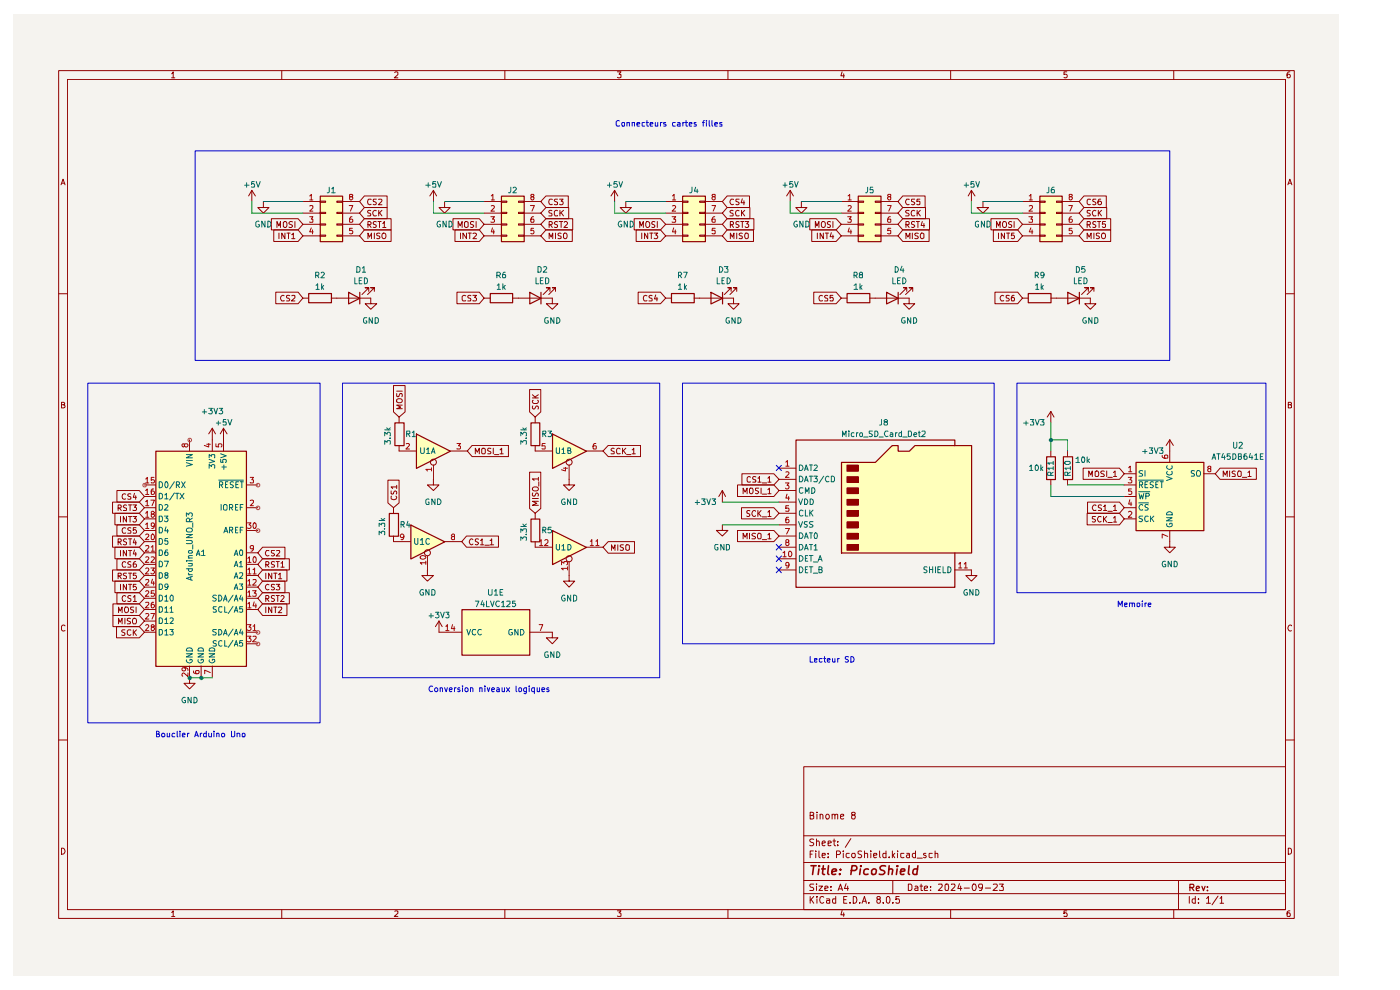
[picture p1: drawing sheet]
<svg xmlns="http://www.w3.org/2000/svg" width="297mm" height="210mm" viewBox="0 0 297 210" stroke-linecap="round" stroke-linejoin="round" font-family="sans-serif">
<path d="M2.9 3h281.2v203.8h-281.2z" fill="#f5f3ef"/>
<g fill="none" stroke="#910000" stroke-width=".21">
<path d="M12.4 15h262.2v179.8h-262.2zM14.3 16.8h258.4v176.2h-258.4zM36.4 15.7l.3-.5v1.3M36.4 16.5h.7M59.8 15v1.8M83.7 15.4l.2-.2h.3l.2 .2v.4l-.8 .7h.8M107.1 15v1.8M131 15.2h.7l-.4 .5 .4 .1v.6h-.7M154.4 15v1.8M178.6 15.2l-.2 .9h.8M179 15.7v.8M201.7 15v1.8"/>
<path d="M226.3 15.2h-.6v.6l.4-.1 .3 .3-.1 .4h-.6M249 15v1.8M273.6 15.2l-.4 .1-.2 .3v.8h.6v-.6l-.4-.1-.2 .3M13 39.2l.4-1.2 .4 1.2M13.1 38.9h.6M273.2 39.2l.4-1.2 .5 1.2M273.3 38.9h.6M12.4 62.3h1.9M272.7 62.3h1.9M13 85.8h.5l.2-.3-.2-.2h-.5v1.2h.5l.3-.4-.3-.3M273.3 85.8h.5l.2-.3-.2-.2h-.5v1.2h.5l.2-.1v-.4l-.3-.2M12.4 109.6h1.9"/>
<path d="M272.7 109.6h1.9M13.8 132.8l-.4-.2-.4 .3 .1 .8 .3 .2 .4-.1M274 132.8l-.2-.2a.6 .6 0 0 0-.6 .7 .6 .6 0 0 0 .8 .5M12.4 157h1.9M272.7 157h1.9M13 179.9a.65 .65 0 0 1 .8 .6 .65 .65 0 0 1-.8 .7zM170.5 162.6h102.2v30.4h-102.2zM170.5 177.3h102.2M171.9 173l.6-.1 .1-.2-.1-.3-.6-.1v1.4h.5l.2-.1v-.5l-.3-.1M172.6 178.1h-.7l-.1 .3 .2 .2 .5 .1 .1 .4-.3 .3-.5-.1M173.2 178.6l.2-.2 .3 .1 .1 .9M173.2 178v1.4"/>
<path d="M173.3 172.3v.1M173.3 172.7v1M174 172.9v-.1a.36 .36 0 0 1 .6 .2v.7M174 172.7v1M174.4 178.9l.7-.2-.2-.3-.4 .1-.1 .7 .3 .2 .3-.1M175.3 172.9l.4-.2a.6 .6 0 0 1 0 1h-.3a.6 .6 0 0 1-.1-.8zM175.7 178.9l.7-.2-.1-.2h-.6v.8h.6M176.5 172.9l.2-.2 .3 .1 .1 .9M176.5 172.7v1M176.7 178.4h.6M177 178v1.2l.3 .2M177.1 173a.36 .36 0 0 1 .6-.2v.9"/>
<path d="M177.7 179.2v.2M177.7 178.5v.1M178.3 173.2l.7-.1v-.3l-.4-.1-.3 .3 .1 .6h.6M180.5 177.9l-1.2 1.8M180.9 172.9l-.2-.2v-.3h.7v.4l-.7 .3 .1 .5a.44 .44 0 0 0 .6-.1 .44 .44 0 0 0-.2-.6M273.3 179.9l.5 .1 .2 .3v.5l-.4 .4h-.3zM36.4 193.5l.3-.3v1.2M36.4 194.4h.7M59.8 193v1.8M83.7 193.3h.7v.4l-.8 .7h.8M107.1 193v1.8M131 193.2h.7l-.4 .4 .4 .2v.5h-.7"/>
<path d="M154.4 193v1.8M170.5 189.6h102.2M170.5 186.8h102.2M170.5 183h102.2M171.9 190.2v1.4M171.9 181.2h.4M172 190.8l.6 .8M172.5 180.5h-.6v1.4M172.6 187.5l-.7 .1v.4l.6 .3 .1 .3-.1 .3h-.7M172.6 190.2l-.7 .8M173.1 180.5v.2M173.1 181v.9"/>
<path d="M173.2 187.5v.1M173.2 188v.9M173.3 190.2v.1M173.3 190.7v.9M173.7 188h.8l-.8 .9h.8M173.7 180.5v1.2l.3 .2M174.4 181.4h.7l-.1-.4h-.5l-.1 .2 .1 .7h.5M174.7 190.3l-.4-.1a.7 .7 0 0 0-.4 .8 .7 .7 0 0 0 .8 .5v-.1M175 188.5l.7-.2-.1-.3h-.6v.9h.6M175.3 190.7h.6l.1 .9M175.7 181.8v.1M175.7 181v.2"/>
<path d="M176 191l-.7 .1v.4h.7M176.3 188.8v.1M176.3 188v.2M177.3 190.7h-.6l-.1 .2 .1 .6h.6M177.3 190.2v1.4M177.5 181.3h.6l.2-.3v-.2l-.2-.3h-.6v1.4M177.8 188.9l.5-1.4 .4 1.4M178 188.5h.6M178.6 193.1l-.2 1h.8M178.9 180.5v.2M178.9 181v.9M179 193.6v.8"/>
<path d="M179 190.8h.5M179.5 187.4l-.3 1.1h.8M179.7 190.2h-.7v1.4h.7M179.8 188v.9M180.2 181h-.5l-.2 .3v.4l.2 .2h.5M180.3 191.4v.2M180.8 181.1l.6-.1v.9a.45 .45 0 0 1-.7-.2zM181 190.2h.4a.75 .75 0 0 1 .4 .8 .75 .75 0 0 1-.8 .6zM182.4 191.4v.2M182.8 180.6l-.5-.1-.3 .2v.3l.8 .5-.3 .4h-.5M182.9 191.6l.5-1.4 .4 1.4M183 191.2h.7"/>
<path d="M183.4 181.1l.6-.1 .1 .9M183.4 180.5v1.4M184.3 191.4v.2M184.7 180.5v.2M184.7 181v.9M185.3 181.4h.7l-.1-.4h-.5l-.1 .2 .1 .7h.5M186.3 190.8l-.3-.3 .3-.3h.4v.5a.56 .56 0 0 0-.6 .2 .56 .56 0 0 0 0 .6h.6l.1-.5-.3-.2M186.6 180.5v1.2l.2 .2M187.4 191.4v.2M188 181h-.6l-.1 .3 .1 .6h.6M188 180.5v1.4M188 190.4l.4-.2a.8 .8 0 0 1 .4 .7 .8 .8 0 0 1-.4 .7l-.4-.3z"/>
<path d="M188.6 181.8v.1M189.3 180.5v1.4M189.4 191.4v.2M189.4 181.4l.4 .5M189.4 186.8v2.8M189.8 181l-.5 .5M190.4 180.5v.2M190.4 181v.9M190.8 190.2h-.7v.6l.1-.1 .6 .1v.7l-.6 .1-.1-.2M191.8 181l-.7 .1v.7l.2 .1h.5M192.4 181h.5l.1 .9M192.7 187.5h.5l.3 .4v.6l-.3 .4h-.5z"/>
<path d="M193 181.4h-.6l-.1 .2 .1 .3h.6M194.1 188h.4l.2 .2v.7h-.6v-.4l.6-.2M194.2 181h-.5l-.2 .3v.4l.3 .2h.4M194.2 180.5v1.4M194.6 182h1.1M195.2 188h.5M195.4 187.5v1.4h.3M196.1 188.5l.7-.2v-.3h-.5l-.2 .2 .1 .7h.6M196.4 181h-.4l-.1 .2 .2 .2 .3 .1v.4h-.5M197.4 188.8v.1M197.4 188v.2M197.8 181l-.7 .1v.7l.3 .1h.4"/>
<path d="M198.4 181.1l.5-.1 .1 .9M198.4 180.5v1.4M199.1 187.6l.7-.1 .1 .4-.9 1h.9M200.6 187.6h.6v.8l-.1 .5h-.4l-.2-.3zM201.7 193v1.8M201.8 187.6l.7-.1 .1 .4-.8 1h.8M203.5 187.4l-.3 1.1h.8M203.8 188v.9M204.6 188.4h1.1M206.4 187.6l.1-.1a.73 .73 0 0 1 .7 .6 .73 .73 0 0 1-.4 .8h-.3l-.3-.5zM208.4 188.1l-.2 .3h-.3l-.3-.3 .2-.6 .6 .1a1.27 1.27 0 0 1-.2 1.3h-.4M209 188.4h1.1"/>
<path d="M210.7 187.6l.7-.1 .2 .4-.1 .2-.9 .8h1M212 187.5h.8l-.4 .5 .4 .2v.6h-.8M226.3 193.2h-.6v.6l.2-.2 .4 .1v.7l-.6-.1M249 193v1.8M250 186.8v6.2M252.3 190.2v1.4M253.6 190.7h-.5l-.2 .2v.4l.2 .3 .5-.1M253.6 190.2v1.4M254.3 191.4v.2M254.3 190.7v.1M255.9 190.6l.5-.4v1.4M255.9 191.6h.9"/>
<path d="M258.4 190.1l-1.3 1.8M258.8 190.6l.4-.4v1.4M258.8 191.6h.8M273.6 193.2l-.6 .3v.8l.6 .1v-.7l-.4-.1-.2 .3"/>
</g>
<path d="M252.4 188.3h.7l.2-.3-.1-.3-.8-.1v1.3M252.8 188.3l.5 .6M253.8 188.5l.7-.2-.2-.3-.4 .1-.1 .7 .1 .1h.5M255 188l.3 .9 .3-.9M256.2 188.8v.1M256.2 188.1v.2" fill="none" stroke="#910000" stroke-width=".25"/>
<g fill="none" stroke="#910000" stroke-width=".34">
<path d="M172 183.6h1.1M172.6 183.6l-.2 1.9M173.7 184.3l-.1 1.2M173.8 183.6l-.1 .2 .2-.1-.1-.1-.1 .2M174.3 184.3h.8M174.7 183.6l-.2 1.6 .4 .3M175.8 183.6l-.2 1.6 .2 .3M176.5 184.9l1-.2-.1-.3a.6 .6 0 0 0-.9 .2v.8h.8M178.1 185.3v.2M178.3 184.4v.2M180.6 184.7l.9-.1 .3-.3-.1-.5-.3-.2h-.6l-.3 1.9M182.5 184.3l-.1 1.2"/>
<path d="M182.6 183.6v.2M184.2 184.4a.65 .65 0 0 0-.9 .3v.6a.64 .64 0 0 0 .8 .1M184.9 184.7l.4-.4 .5 .1 .1 .3-.1 .5a.56 .56 0 0 1-.9 .1zM187.9 183.7l-.8-.1-.4 .4 .1 .4 .7 .3 .2 .5-.4 .3-.8-.1M188.5 184.5l.1-.1a.48 .48 0 0 1 .8 .2l-.2 .9M188.6 183.6l-.1 1.9M190.3 184.3l-.1 1.2M190.4 183.6l-.2 .1h.3l-.1-.1-.1 .2M191 184.9l.9-.2v-.3l-.6-.1-.2 .3v.8h.7M192.9 183.6l-.2 1.6 .3 .3M194.6 184.4l-.5-.1-.4 .4v.6l.3 .2 .5-.1M194.7 183.6l-.2 1.9"/>
</g>
<g fill="#ffb">
<path d="M144.8 41.6h4.8v9.6h-4.8z"/>
<path d="M241 98h14.4v14.5h-14.4z"/>
<path d="M178.5 98h7.2l3.5-3.5h1.3v1.2h2.4l1.2-1.2h12v22.8h-27.6z"/>
<path d="M33 95.7h19.2v45.6h-19.2z"/>
<path d="M87.1 111.3l7.2 3.6-7.2 3.6z"/>
<path d="M117.2 112.5l7.2 3.6-7.2 3.6z"/>
<path d="M117.2 92l7.2 3.7-7.2 3.6z"/>
<path d="M88.3 92l7.2 3.7-7.2 3.6z"/>
<path d="M98 129.3h14.3v9.6h-14.3z"/>
<path d="M67.9 41.6h4.7v9.6h-4.7z"/>
<path d="M106.3 41.6h4.9v9.6h-4.9z"/>
<path d="M220.6 41.6h4.7v9.6h-4.7z"/>
<path d="M182 41.6h4.9v9.6h-4.9z"/>
</g>
<g fill="none" stroke="#910000" stroke-width=".21">
<path d="M115.8 48.8h5.6v2.4h-5.6l-1.1-1.2zM115.8 44h4.8v2.4h-4.8l-1.1-1.2zM115.8 46.4h5.7v2.4h-5.7l-1.1-1.2zM115.8 41.6h4.8v2.4h-4.8l-1.1-1.2zM116.5 50.6v-1.2l.4 .9 .4-.9v1.2M116.5 47.7l.6-.1v-.5l-.6-.1v1.3M116.8 47.7l.4 .6M117.1 44.7l-.4-.1-.3 .3 .1 .2 .6 .3v.3l-.7 .1M117.2 42.3l-.5-.1a.67 .67 0 0 0-.3 .7 .67 .67 0 0 0 .5 .5l.3-.1M117.9 49.4v1.2M118.3 44.7a.45 .45 0 0 0-.7 .2v.6l.2 .3 .5-.1M118.3 47.1l-.4-.1-.3 .2 .2 .4 .5 .1v.4l-.2 .2-.5-.1"/>
<path d="M118.3 42.2h-.5l-.2 .2 .2 .4 .5 .1v.4h-.7M118.6 47h.8M118.7 42.2h.8l-.5 .5 .4 .1v.5h-.7M118.8 44.6v1.2M119 49.5l-.4-.1-.2 .3v.3l.6 .2v.3h-.6M119 45.1l.5 .7M119 47v1.3M119.5 49.6l.6-.2a.65 .65 0 0 1 .2 .7 .65 .65 0 0 1-.5 .5l-.3-.1zM119.5 44.6l-.7 .7M119.7 47.2l.4-.2 .3 .4-.8 .9h.8M130.4 40.4l-.8 1.2M130.4 40.4v2.4"/>
<path d="M130.4 40.4l.7 1.2M132.8 42.8v1.2h1.1l-1.1 1.2-1.2-1.2h1.2M134.5 46.4h5.6l1.1 1.2-1.1 1.2h-5.6zM135 48.8h5.1l1.1 1.2-1.1 1.2h-5.1zM135.7 48.3v-1.3l.4 .9 .4-.9v1.3M136.1 49.4v1.2M137.2 47l.4 .1a.74 .74 0 0 1 .1 1l-.5 .2a.86 .86 0 0 1 0-1.3zM137.4 49.4v1.2l-.7-1.2v1.2M137.8 49.4h.7M138.2 49.4v1.2M138.8 49.4h.7l-.4 .5 .4 .2-.1 .4h-.6M138.9 47.1l-.4-.1-.2 .2v.4l.6 .1v.5h-.6"/>
<path d="M139.4 47v1.3M141.2 42.8h3.6M141.2 45.2h3.6M141.2 47.6h3.6M141.2 50h3.6M144.8 49.9h1.2v.2h-1.2zM144.8 47.5h1.2v.2h-1.2zM144.8 45h1.2v.3h-1.2zM144.8 42.7h1.2v.2h-1.2zM148.4 49.9h1.2v.2h-1.2zM148.4 47.5h1.2v.2h-1.2zM148.4 45h1.2v.3h-1.2z"/>
<path d="M148.4 42.7h1.2v.2h-1.2zM149.6 42.8h3.6M149.6 45.2h3.6M149.6 47.6h3.6M149.6 50h3.6M154.3 44h4.8v2.4h-4.8l-1.1-1.2zM154.3 41.6h4.7v2.4h-4.7l-1.1-1.2zM154.3 48.8h5.5v2.4h-5.5l-1.1-1.2zM154.3 46.4h5.6v2.4h-5.6l-1.1-1.2zM154.9 50.6v-1.2l.5 .9 .3-.9v1.2M154.9 47.7l.6-.1v-.5l-.6-.1v1.3M155.2 47.7l.4 .6"/>
<path d="M155.5 44.7l-.4-.1-.2 .3 .2 .3 .4 .2v.3l-.6 .1M155.6 42.3l-.5-.1a.67 .67 0 0 0-.2 .7 .67 .67 0 0 0 .5 .5l.2-.1M156.3 49.4v1.2M156.8 44.7l-.3-.1a.67 .67 0 0 0-.5 .5 .67 .67 0 0 0 .3 .7l.5-.1M156.8 42.2h-.6l-.1 .5a.57 .57 0 0 1 .6 .6h-.6M156.8 47.1l-.5-.1-.2 .2v.3l.7 .4-.3 .4-.4-.1M157.1 47h.7M157.3 44.6v1.2M157.5 42.2l-.3 .8h.8M157.5 49.5l-.4-.1-.3 .3 .3 .3 .4 .2v.3h-.7M157.5 45.1l.5 .7M157.5 47v1.3"/>
<path d="M157.8 42.6v.8M158 44.6l-.7 .7M158.1 47h.7l-.4 .5 .4 .2-.1 .5-.5 .1-.1-.2M158.2 49.4l.5 .2v.9l-.5 .1a.78 .78 0 0 1 0-1.2zM167.6 40.4l-.7 1.2M167.6 40.4v2.4M167.6 40.4l.7 1.2M170 42.8v1.2h1.2l-1.2 1.2-1.2-1.2h1.2M117.2 63.2v1.2h1.2l-1.2 1.2-1.3-1.2h1.3M135.4 62h4.7l1.1 1.2-1.1 1.2h-4.7zM137.2 62.7h-.2a.67 .67 0 0 0-.5 .5 .67 .67 0 0 0 .2 .6h.5M138.3 62.7h-.4l-.2 .2 .2 .3 .4 .2v.4h-.6"/>
<path d="M139.1 62.6l-.2 .8h.6M139.4 63.1v.7M141.2 63.2h1.2M147.2 63.2h8.4v1.2h1.2l-1.2 1.2-1.2-1.2h1.2M155.1 61.8v-.8h-.7h.7l-1.4 1.5M156.3 61.8v-.8h-.7h.7l-1.4 1.5M129 94.5h6.9v2.4h-6.9l-1.1-1.2zM130.3 95.2l-.4-.1-.3 .2 .1 .3 .6 .2v.4l-.7 .1M131.6 95.2l-.5-.1-.3 .3v.6l.2 .3 .6-.1M132.1 95.1v1.2M132.2 95.6l.6 .7M132.8 95.1l-.7 .7"/>
<path d="M132.9 96.4h1M134.1 95.4l.3-.3v1.2M134.1 96.3h.7M222.9 87.3v2.4M222.9 95.7v1.2M222.9 87.3l-.7 1.2M222.9 87.3l.7 1.2M226.5 95.7v1.2M229.8 99.3h7.7l1 1.2-1 1.2h-7.7zM234.3 100h-.7l-.1 .2 .3 .3h.2l.3 .4-.2 .2h-.6M234.8 99.9v1.2M248.2 93.3v4.7"/>
<path d="M248.2 93.3l-.8 1.2M248.2 93.3l.7 1.2M258.8 99.3h7.7v2.4h-7.7l-1-1.2zM260.9 99.9v1.2M262 100l-.4-.1-.2 .3 .2 .3 .4 .2v.3l-.6 .1M262.8 99.9l.5 .2v.8l-.2 .2h-.4a.86 .86 0 0 1 .1-1.2zM120.7 101.7v1.2h1.2l-1.2 1.2-1.2-1.2h1.2M153.2 104.1l-.7 1.2M153.2 104.1v2.4M153.2 104.1l.7 1.2M156.5 102.9h7.7l1.1 1.2-1.1 1.2h-7.7zM157.3 107.7h6.9l1.1 1.2-1.1 1.2h-6.9z"/>
<path d="M157.4 100.5h6.8l1.1 1.2-1.1 1.2h-6.8zM157.6 104.7v-1.2l.5 .9 .4-.9v1.2M159 103.7l.2-.2h.4a.86 .86 0 0 1-.1 1.2l-.5-.1zM159.1 108.4h-.6v.5l.5 .1 .1 .3-.3 .3-.4-.1M159.2 101.3l-.4-.2-.3 .3v.6l.2 .3 .5-.1M160.3 108.5l-.3-.2a.61 .61 0 0 0-.5 .7 .61 .61 0 0 0 .8 .5v-.1M160.4 101.2l-.6-.1-.1 .2v.3l.6 .2 .1 .1-.1 .4h-.6M160.8 101.4h.1l.2-.3v1.2M160.8 102.3h.7M160.8 108.3v1.3M160.9 103.5l-.6 .1v.4l.6 .4-.2 .3-.4-.1M160.9 108.9l.6 .7"/>
<path d="M161.5 108.3l-.7 .7M161.5 103.5v1.2M161.7 102.4h.9M161.7 109.6h.9M161.7 104.8h.9M162.9 101.4l.3-.3v1.2M162.9 108.6l.3-.3v1.3M162.9 103.9l.3-.4v1.2M162.9 102.3h.7M162.9 109.6h.7M162.9 104.7h.7M222.9 101.7v1.2"/>
<path d="M226.5 101.7v1.2M230.6 108.9h6.9l1 1.2-1 1.2h-6.9zM230.7 106.5h6.8l1 1.2-1 1.2h-6.8zM231 101.1v-1.2l.4 .9 .3-.9v1.2M232.3 100.1l.5-.2a.86 .86 0 0 1 .1 1.2h-.4l-.2-.2zM232.4 109.6h-.7v.4l.7 .4-.2 .3h-.5M232.5 107.3l-.2-.2a.66 .66 0 0 0-.6 .5 .66 .66 0 0 0 .3 .7l.5-.1M233.6 109.6h-.5a.67 .67 0 0 0-.3 .6 .67 .67 0 0 0 .5 .5l.3-.1M233.7 107.2l-.5-.1-.2 .2v.3l.7 .3-.2 .4h-.5M234.1 107.4h.2l.1-.3v1.2M234.1 109.6v1.1M234.1 108.3h.7"/>
<path d="M234.3 110.1l.5 .6M234.8 109.6l-.7 .6M235 110.8h1M235 108.5h1M235 101.3h1M236.2 109.9l.4-.3v1.1M236.2 107.4l.4-.3v1.2M236.2 100.2l.4-.3v1.2M236.2 110.7h.7M236.2 108.3h.7M236.2 101.1h.7M238.5 100.5h2.5"/>
<path d="M238.5 110.1h2.5M238.5 102.9h2.5M238.5 107.7h2.5M238.5 105.3h2.5M248.2 112.5v3.6h1.1l-1.1 1.2-1.2-1.2h1.2M255.4 100.5h2.4M259.5 101.1v-1.2l.4 .9 .4-.9v1.2M263.6 101.3h.9M264.7 100.2l.4-.3v1.2M264.7 101.1h.7M206.1 120.9v1.2h1.2l-1.2 1.2-1.2-1.2h1.2"/>
</g>
<path d="M144.8 41.6h4.8v9.7h-4.8zM142.4 62.3h4.9v1.9h-4.9zM150.8 62l2.5 1.3-2.5 1.2zM153.3 62v2.5M222 96.9h1.9v4.8h-1.9zM225.6 96.9h1.9v4.8h-1.9zM241 98.1h14.4v14.5h-14.4zM179.7 115.5h2.4v1.2h-2.4z" fill="none" stroke="#910000" stroke-width=".25"/>
<g fill="none" stroke="#b90000" stroke-width=".21">
<path d="M142.6 46h.7l-.4 .5h.4v.7l-.7-.1M142.7 41.6l.3-.4v1.2M142.7 43.7l.4-.1 .2 .3-.7 .9h.7M142.7 42.4h.6M142.9 48.3l-.2 .9h.7M143.3 48.8v.8M151 43.6h.8l-.5 1.2M151.3 41.7l-.3-.3 .2-.2h.4l.1 .4-.7 .3v.3l.3 .2 .4-.2v-.4l-.1-.1M151.6 46l-.4 .1-.2 .9 .2 .2 .5-.1-.1-.6h-.4l-.2 .1M151.7 48.4h-.6l-.1 .5h.7v.6h-.7M239.4 99.2l.4-.3v1.2M246.5 96.6l.1 .4 .3 .2h.7l.1-.6h-.6v.5l.1 .1"/>
<path d="M256.5 99.4l-.3-.3 .3-.2 .4 .1v.3a.51 .51 0 0 0-.6 .7h.6v-.5l-.2-.1M239.3 101.3h.8l-.4 .5 .4 .1v.4l-.2 .1h-.6M239.4 108.6l.5-.1 .2 .4-.8 .8h.8M239.4 100.1h.7M239.7 106l-.3 .9h.7M239.9 106.5v.8M240 103.7h-.6v.5l.5-.1 .2 .3-.1 .4h-.6M247.7 113.8l-1.2-.5v.8"/>
</g>
<g fill="none" stroke="#006665" stroke-width=".21">
<path d="M242.4 99.9h-.7l-.1 .3 .3 .2h.2l.3 .4-.2 .2h-.6M242.9 99.8v1.2M247.6 100l-.1 .2a.67 .67 0 0 0 .5 .6 .67 .67 0 0 0 .7-.3l-.1-.5M247.6 98.8l-.1 .3a.67 .67 0 0 0 .5 .5 .67 .67 0 0 0 .7-.3l-.1-.5M253.4 99.9h-.7v.3l.7 .5-.2 .3h-.5M254.1 99.8a.46 .46 0 0 1 .6 .4l-.2 .8h-.5a.86 .86 0 0 1 .1-1.2zM241.6 101.9h5.2M241.6 106.7h2.1M241.6 104.3h2.3M241.6 104.6l.3 1.2 .2-.8 .3 .8 .3-1.2M241.7 102.9l.7-.1v-.4l-.2-.2h-.5v1.3M242.1 102.9l.3 .6"/>
<path d="M242.4 109.5h-.6l-.2 .1 .2 .4 .6 .3-.3 .4-.5-.1M242.4 107.2l-.2-.2a.66 .66 0 0 0-.6 .5 .66 .66 0 0 0 .3 .7l.5-.1M242.9 102.8h.4M243.1 105.2h.6l.1-.1v-.4l-.7-.1v1.2M243.5 102.2h-.6v1.3h.6M243.6 109.6l-.5-.1a.67 .67 0 0 0-.3 .6 .67 .67 0 0 0 .5 .6l.3-.2M243.6 107.1l-.5-.1-.2 .2v.3l.7 .4-.2 .3h-.5M244.1 109.5v1.2M244.3 110l.5 .7M244.7 102.3l-.5-.1-.2 .2v.3l.7 .4-.3 .4-.4-.1M244.8 109.5l-.7 .6M245.2 102.8h.3"/>
<path d="M245.7 102.2h-.5v1.3h.5M246.1 102.2h.7M246.5 102.2v1.3M247.5 101.1l1.2 .4-1.2 .4M247.5 109.8h1.2l-1.2 .7h1.2M247.6 111.1l-.1 .1a.66 .66 0 0 0 .5 .5 .66 .66 0 0 0 .7-.2l-.1-.5h-.4v.2M247.6 108.8l.4-.3 .4 .1 .3 .2v.4h-1.2z"/>
</g>
<path d="M179.7 115.5h2.4v1.2h-2.4z" fill="#910000"/>
<path d="M179.7 113.2h2.4v1.1h-2.4z" fill="none" stroke="#910000" stroke-width=".25"/>
<path d="M179.7 113.2h2.4v1.1h-2.4z" fill="#910000"/>
<path d="M179.7 110.7h2.4v1.3h-2.4z" fill="none" stroke="#910000" stroke-width=".25"/>
<path d="M179.7 110.7h2.4v1.3h-2.4z" fill="#910000"/>
<path d="M179.7 108.3h2.4v1.2h-2.4z" fill="none" stroke="#910000" stroke-width=".25"/>
<path d="M179.7 108.3h2.4v1.2h-2.4z" fill="#910000"/>
<path d="M179.7 106h2.4v1.1h-2.4z" fill="none" stroke="#910000" stroke-width=".25"/>
<path d="M179.7 106h2.4v1.1h-2.4z" fill="#910000"/>
<path d="M179.7 103.5h2.4v1.2h-2.4z" fill="none" stroke="#910000" stroke-width=".25"/>
<path d="M179.7 103.5h2.4v1.2h-2.4z" fill="#910000"/>
<path d="M179.7 101.1h2.4v1.2h-2.4z" fill="none" stroke="#910000" stroke-width=".25"/>
<path d="M179.7 101.1h2.4v1.2h-2.4z" fill="#910000"/>
<path d="M179.7 98.7h2.4v1.2h-2.4z" fill="none" stroke="#910000" stroke-width=".25"/>
<path d="M179.7 98.7h2.4v1.2h-2.4z" fill="#910000"/>
<g fill="none" stroke="#910000" stroke-width=".25">
<path d="M67.9 41.6h4.8v9.7h-4.8zM106.4 41.6h4.8v9.7h-4.8zM182.1 41.6h4.8v9.7h-4.8zM220.6 41.6h4.7v9.7h-4.7zM65.5 62.3h4.8v1.9h-4.8zM74 62l2.3 1.3-2.3 1.2zM76.3 62v2.5M104 62.3h4.8v1.9h-4.8zM112.4 62l2.4 1.3-2.4 1.2zM114.8 62v2.5M179.7 62.3h4.8v1.9h-4.8zM188.1 62l2.4 1.3-2.4 1.2z"/>
<path d="M190.5 62v2.5M218.1 62.3h4.9v1.9h-4.9zM226.5 62l2.5 1.3-2.5 1.2zM229 62v2.5M33.1 95.7h19.2v45.6h-19.2zM83.8 89.7h1.9v4.8h-1.9zM88.3 92.1l7.2 3.6-7.2 3.7zM112.6 89.7h1.9v4.8h-1.9zM117.2 92.1l7.2 3.6-7.2 3.7zM178.5 98.1h7.2l3.6-3.6h1.2v1.2h2.4l1.2-1.2h12v22.8h-27.6zM202.6 94.5v-1.2h-33.7v31.3h33.7v-7.3M82.6 108.9h1.9v4.8h-1.9z"/>
<path d="M87.2 111.4l7.2 3.5-7.2 3.7zM112.6 110.1h1.9v4.8h-1.9zM117.2 112.6l7.2 3.5-7.2 3.7zM98 129.3h14.4v9.7h-14.4z"/>
</g>
<g fill="none" stroke="#910000" stroke-width=".21">
<path d="M53.4 40.4l-.7 1.2M53.4 40.4v2.4M53.4 40.4l.8 1.2M55.9 42.8v1.2h1.2l-1.2 1.2-1.2-1.2h1.2M57.6 46.4h5.6l1.1 1.2-1.1 1.2h-5.6zM58.1 48.8h5.1l1.1 1.2-1.1 1.2h-5.1zM58.8 48.3v-1.3l.4 .9 .3-.9v1.3M59.2 49.4v1.2M60.1 47.2l.5-.2a.86 .86 0 0 1 0 1.3l-.5-.2zM60.4 49.4v1.2l-.6-1.2v1.2M60.9 49.4h.6M61.2 49.4v1.2"/>
<path d="M61.9 49.8l.3-.4v1.2M61.9 50.6h.7M62.1 47.1l-.6-.1-.2 .2 .2 .4 .6 .3-.3 .4-.5-.1M62.6 47v1.3M64.3 42.8h3.6M64.3 45.2h3.6M64.3 47.6h3.6M64.3 50h3.6M67.9 49.9h1.2v.2h-1.2zM67.9 47.5h1.2v.2h-1.2zM67.9 45h1.2v.3h-1.2zM67.9 42.7h1.2v.2h-1.2z"/>
<path d="M71.5 49.9h1.1v.2h-1.1zM71.5 47.5h1.1v.2h-1.1zM71.5 45h1.1v.3h-1.1zM71.5 42.7h1.1v.2h-1.1zM72.6 42.8h3.7M72.6 45.2h3.7M72.6 47.6h3.7M72.6 50h3.7M77.3 48.8h5.7v2.4h-5.7l-1-1.2zM77.3 44h4.8v2.4h-4.8l-1-1.2zM77.3 46.4h5.7v2.4h-5.7l-1-1.2zM77.3 41.6h4.8v2.4h-4.8l-1-1.2z"/>
<path d="M78.1 50.6v-1.2l.3 .9 .4-.9v1.2M78.1 47.7l.6-.1v-.4l-.2-.2h-.4v1.3M78.3 47.7l.4 .6M78.7 44.7h-.6v.4a.47 .47 0 0 1 .4 .2 .47 .47 0 0 1 .1 .5h-.6M78.7 42.3l-.5-.1a.67 .67 0 0 0-.2 .7 .67 .67 0 0 0 .5 .5l.2-.1M79.4 49.4v1.2M79.8 44.7a.61 .61 0 0 0-.7 .3 .61 .61 0 0 0 .2 .8l.5-.1M79.8 47.1h-.6v.5l.6 .1v.3l-.2 .3-.4-.1M79.8 42.2h-.6v.6l.6 .1v.3l-.2 .2-.4-.1M80.2 47h.7M80.3 42.3l.6-.1 .1 .4-.7 .8h.7M80.3 44.6v1.2"/>
<path d="M80.5 45.1l.5 .7M80.5 47v1.3M80.6 49.5h-.7v.4l.7 .4-.3 .3-.4-.1M81 44.6l-.7 .7M81.1 49.6l.3-.2a.6 .6 0 0 1 .5 .6 .6 .6 0 0 1-.5 .6l-.4-.4zM81.2 47.4l.3-.4v1.3M81.2 48.3h.7M91.9 40.4v2.4M91.9 40.4l-.7 1.2M91.9 40.4l.7 1.2M94.3 42.8v1.2h1.2l-1.2 1.2-1.2-1.2h1.2M96.1 46.4h5.6l1 1.2-1 1.2h-5.6z"/>
<path d="M96.5 48.8h5.2l1 1.2-1 1.2h-5.2zM97.2 48.3v-1.3l.4 .9 .4-.9v1.3M97.7 49.4v1.2M98.5 47.2l.3-.2 .5 .2v.9l-.2 .2-.6-.2zM99 49.4v1.2l-.8-1.2v1.2M99.3 49.4h.7M99.6 49.4v1.2M100.3 49.5l.5-.1 .3 .3-.8 .9h.8M100.5 47.1l-.5-.1-.2 .2v.3l.7 .4-.3 .4-.4-.1M101 47v1.3M102.7 42.8h3.6M102.7 45.2h3.6"/>
<path d="M102.7 47.6h3.6M102.7 50h3.6M106.3 49.9h1.2v.2h-1.2zM106.3 47.5h1.2v.2h-1.2zM106.3 45h1.2v.3h-1.2zM106.3 42.7h1.2v.2h-1.2zM110 49.9h1.2v.2h-1.2zM110 47.5h1.2v.2h-1.2zM110 45h1.2v.3h-1.2zM110 42.7h1.2v.2h-1.2zM111.2 42.8h3.5M111.2 45.2h3.5"/>
<path d="M111.2 47.6h3.5M111.2 50h3.5M171.8 46.4h5.6l1.1 1.2-1.1 1.2h-5.6zM172.2 48.8h5.2l1.1 1.2-1.1 1.2h-5.2zM173 48.3v-1.3l.3 .9 .4-.9v1.3M173.4 49.4v1.2M174.3 47.2l.3-.2 .4 .2 .1 .6-.4 .5-.4-.2zM174.7 49.4v1.2l-.7-1.2v1.2M175.1 49.4h.7M175.4 49.4v1.2M176.2 47.1h-.6v.5l.5 .1 .1 .3-.3 .3-.4-.1M176.4 49.4l-.3 .8h.8"/>
<path d="M176.7 47v1.3M176.7 49.9v.7M178.5 42.8h3.5M178.5 45.2h3.5M178.5 47.6h3.5M178.5 50h3.5M182 49.9h1.2v.2h-1.2zM182 47.5h1.2v.2h-1.2zM182 45h1.2v.3h-1.2zM182 42.7h1.2v.2h-1.2zM185.7 49.9h1.2v.2h-1.2zM185.7 47.5h1.2v.2h-1.2z"/>
<path d="M185.7 45h1.2v.3h-1.2zM185.7 42.7h1.2v.2h-1.2zM186.9 42.8h3.6M186.9 45.2h3.6M186.9 47.6h3.6M186.9 50h3.6M191.5 46.4h5.7v2.4h-5.7l-1-1.2zM191.5 41.6h4.8v2.4h-4.8l-1-1.2zM191.5 44h4.8v2.4h-4.8l-1-1.2zM191.5 48.8h5.6v2.4h-5.6l-1-1.2zM192.2 47.7l.7-.1v-.4l-.2-.2h-.5v1.3M192.2 50.6v-1.2l.4 .9 .4-.9v1.2"/>
<path d="M192.4 47.7l.5 .6M192.9 42.3l-.5-.1a.66 .66 0 0 0-.3 .8 .66 .66 0 0 0 .6 .4l.2-.1M192.9 44.7h-.7l-.1 .3 .3 .2h.2l.3 .4-.2 .2h-.6M193.5 49.4v1.2M194.1 47.1l-.6-.1-.1 .2v.3l.7 .4-.3 .4-.4-.1M194.1 42.2h-.6l-.1 .5a.57 .57 0 0 1 .6 .6h-.6M194.1 44.7l-.3-.1a.67 .67 0 0 0-.5 .5 .67 .67 0 0 0 .2 .7l.6-.1M194.4 47h.7M194.6 44.6v1.2M194.7 47v1.3M194.7 45.1l.5 .7M194.8 49.5l-.5-.1-.2 .3 .2 .3h.3l.2 .3-.1 .2h-.6"/>
<path d="M195.2 42.2h-.6l-.1 .6h.7v.5h-.7M195.2 44.6l-.6 .7M195.3 49.6l.2-.2 .5 .2v.9l-.5 .1a.82 .82 0 0 1-.2-1zM195.7 47l-.3 .8h.8M196 47.4v.9M206.1 40.4l-.7 1.2M206.1 40.4v2.4M206.1 40.4l.7 1.2M208.5 42.8v1.2h1.2l-1.2 1.2-1.2-1.2h1.2M210.2 46.4h5.7l1 1.2-1 1.2h-5.7zM210.7 48.8h5.2l1 1.2-1 1.2h-5.2zM211.4 48.3v-1.3l.4 .9 .4-.9v1.3"/>
<path d="M211.8 49.4v1.2M212.8 47.2l.2-.2 .4 .2 .1 .6-.3 .5-.4-.2zM213.1 49.4v1.2l-.7-1.2v1.2M213.5 49.4h.7M213.9 49.4v1.2M214.6 47.1l-.4-.1-.3 .2 .2 .4 .5 .1v.4l-.1 .2-.6-.1M215.1 49.4h-.5l-.1 .6 .2-.1 .4 .1v.5h-.6M215.1 47v1.3M216.9 42.8h3.7M216.9 45.2h3.7M216.9 47.6h3.7M216.9 50h3.7"/>
<path d="M220.6 49.9h1.1v.2h-1.1zM220.6 47.5h1.1v.2h-1.1zM220.6 45h1.1v.3h-1.1zM220.6 42.7h1.1v.2h-1.1zM224.1 49.9h1.2v.2h-1.2zM224.1 47.5h1.2v.2h-1.2zM224.1 45h1.2v.3h-1.2zM224.1 42.7h1.2v.2h-1.2zM225.3 42.8h3.6M225.3 45.2h3.6M225.3 47.6h3.6M225.3 50h3.6"/>
<path d="M230 48.8h5.6v2.4h-5.6l-1.1-1.2zM230 46.4h5.6v2.4h-5.6l-1.1-1.2zM230 44h4.8v2.4h-4.8l-1.1-1.2zM230 41.6h4.7v2.4h-4.7l-1.1-1.2zM230.6 50.6v-1.2l.5 .9 .4-.9v1.2M230.6 47.7l.7-.1v-.4l-.2-.2h-.5v1.3M231 47.7l.3 .6M231.3 44.7h-.7v.3l.7 .5-.2 .3h-.5M231.3 42.3l-.5-.1-.2 .3 .1 .8 .3 .1 .3-.1M232.1 49.4v1.2M232.5 47.1h-.6v.5l.5 .1 .1 .3-.3 .3-.4-.1M232.5 44.7a.61 .61 0 0 0-.8 .3 .61 .61 0 0 0 .3 .8l.5-.1"/>
<path d="M232.5 42.2h-.6v.6l.5 .1 .1 .3-.3 .2-.4-.1M232.8 47h.7M233 44.6v1.2M233.2 47v1.3M233.2 45.1l.5 .7M233.3 49.5h-.7v.4l.7 .4-.3 .3-.4-.1M233.5 42.2h-.3l-.2 .3v.8a.42 .42 0 0 0 .6 0 .42 .42 0 0 0 0-.5l-.4-.1-.3 .2M233.7 44.6l-.7 .7M233.8 49.6l.2-.2a.6 .6 0 0 1 .5 .6 .6 .6 0 0 1-.5 .6l-.3-.4zM234.5 47h-.6l-.1 .6h.7v.5l-.1 .2h-.4l-.2-.2M58.5 62h4.7l1.1 1.2-1.1 1.2h-4.7zM60.3 62.7a.61 .61 0 0 0-.8 .3 .61 .61 0 0 0 .3 .8h.5"/>
<path d="M61.5 62.7h-.7v.4l.7 .4-.2 .3h-.5M61.9 62.7h.7v.5l-.8 .6h.8M64.3 63.2h1.1M70.3 63.2h8.4v1.2h1.2l-1.2 1.2-1.2-1.2h1.2M78.2 61.8v-.8h-.7h.7l-1.4 1.5M79.4 61.8v-.8h-.7h.7l-1.4 1.5M96.9 62h4.8l1 1.2-1 1.2h-4.8zM98.8 62.7h-.1a.45 .45 0 0 0-.7 .2v.7l.2 .2h.6M99.9 62.7h-.6v.5a.47 .47 0 0 1 .5 .1 .47 .47 0 0 1 0 .5h-.6M100.3 62.7h.8l-.4 .4 .4 .2-.1 .5h-.7M102.7 63.2h1.3M108.7 63.2h8.5"/>
<path d="M116.7 61.8v-.8h-.8h.8l-1.5 1.5M117.9 61.8v-.8h-.7h.7l-1.5 1.5M172.6 62h4.8l1.1 1.2-1.1 1.2h-4.8zM174.5 62.7h-.3a.67 .67 0 0 0-.5 .5 .67 .67 0 0 0 .3 .6h.5M175.6 62.7h-.4l-.3 .2 .3 .3 .4 .2v.4h-.7M176.7 62.7h-.6v.5a.45 .45 0 0 1 .6 0 .45 .45 0 0 1 0 .6h-.6M178.5 63.2h1.2M184.5 63.2h8.4v1.2h1.2l-1.2 1.2-1.2-1.2h1.2M192.4 61.8v-.8h-.7h.7l-1.5 1.5M193.6 61.8v-.8h-.7h.7l-1.5 1.5M211.1 62h4.8l1 1.2-1 1.2h-4.8zM212.9 62.7a.61 .61 0 0 0-.7 .3 .61 .61 0 0 0 .2 .8h.5"/>
<path d="M214.1 62.7h-.7v.4l.7 .4-.2 .3h-.5M215.1 62.7h-.4l-.2 .5 .1 .6h.5a.43 .43 0 0 0 .1-.5 .43 .43 0 0 0-.6-.1l-.1 .1M216.9 63.2h1.2M222.9 63.2h8.4v1.2h1.2l-1.2 1.2-1.2-1.2h1.2M230.9 61.8v-.8h-.8h.8l-1.5 1.5M232.1 61.8v-.8h-.8h.8l-1.5 1.5M40.2 93.3v2.4M45 90.8v4.9M45 90.8l-.7 1.2M45 90.8l.7 1.2M47.4 90.8v4.9M47.4 90.8l-.7 1.2"/>
<path d="M47.4 90.8l.8 1.2M83.5 81.8h2.4v5.6l-1.2 1.1-1.2-1.1zM84.2 84.7a.77 .77 0 0 1 1.1 .2v.4a.72 .72 0 0 1-1.1-.2zM84.2 83.5v.6l.1 .1 .4-.1 .1-.6h.5v.7M84.2 83h1.1M84.7 94.5v1.2h3.6M84.7 88.5v1.2M85.3 85.9h-1.1l.8 .5-.8 .3h1.1M91.9 98.6v4.3h1.2l-1.2 1.2-1.2-1.2h1.2M95.5 95.7h3.6M100.2 94.5h7.7v2.4h-7.7l-1.1-1.2zM100.8 96.3v-1.2l.5 .8 .4-.8v1.2"/>
<path d="M102.2 95.2l.2-.1 .6 .1v.9l-.2 .2h-.4l-.2-.2zM104.1 95.2l-.5-.1-.1 .1v.4l.6 .3-.1 .4h-.5M104.6 95.1v1.2M104.9 96.4h.9M106.1 95.4l.3-.3v1.2M106.1 96.3h.7M112.3 82.6h2.4v4.8l-1.2 1.1-1.2-1.1zM112.9 84.4h1.3M112.9 83.7l.8 .7M113 86.1v.6h.5l.2-.5 .3-.1 .2 .3-.1 .4M113.1 84.9l-.2 .4 .4 .3 .7-.1 .2-.2-.2-.4M113.5 94.5v1.2h3.7"/>
<path d="M113.5 88.5v1.2M114.2 83.7l-.7 .5M120.7 98.6v3.1M124.4 95.7h3.5M165.3 99.3h3.5M23.9 106.5h5.6l1.1 1.2-1.1 1.2h-5.6zM23.9 113.7h5.6l1.1 1.2-1.1 1.2h-5.6zM24.4 116.1h5.1l1.1 1.2-1.1 1.2h-5.1zM24.4 108.9h5.1l1.1 1.2-1.1 1.2h-5.1zM24.8 111.3h4.7l1.1 1.2-1.1 1.2h-4.7zM24.8 118.5h4.7l1.1 1.2-1.1 1.2h-4.7zM24.8 104.1h4.7l1.1 1.2-1.1 1.2h-4.7z"/>
<path d="M25.1 107.8l.6-.1v-.5l-.6-.1v1.2M25.1 115l.6-.1v-.5l-.6-.1v1.3M25.3 107.8l.4 .5M25.3 115l.4 .6M25.6 109.6v1.1M25.6 116.8v1.1M26.7 112l-.3-.1a.67 .67 0 0 0-.5 .5 .67 .67 0 0 0 .3 .7l.5-.1M26.7 119.3l-.3-.2a.67 .67 0 0 0-.5 .5 .67 .67 0 0 0 .3 .7l.5-.1M26.7 104.8l-.3-.1a.6 .6 0 0 0-.5 .6 .6 .6 0 0 0 .5 .6l.3-.1M26.8 107.2l-.4-.1-.2 .3v.2l.6 .3v.3l-.6 .1M26.8 114.4l-.4-.1-.2 .3v.2l.6 .3v.3l-.1 .2-.5-.1M26.8 116.8v1.1l-.6-1.1v1.1"/>
<path d="M26.8 109.6v1.1l-.6-1.1v1.1M27.3 114.3h.6M27.3 107.1h.6M27.3 116.8h.6M27.3 109.6h.6M27.6 107.1v1.2M27.6 109.6v1.1M27.6 114.3v1.3M27.6 116.8v1.1M27.8 112l-.5-.1-.2 .3 .2 .3 .5 .2v.3l-.7 .1M27.8 119.2l-.5-.1-.2 .3 .1 .2 .6 .3v.3l-.7 .1M27.8 104.8l-.5-.1-.2 .3 .2 .3 .5 .2v.3h-.7"/>
<path d="M28.2 107.1h.8l-.5 .5 .5 .2v.3l-.2 .2-.6-.1M28.2 109.6h.8l-.5 .4 .4 .1 .1 .4-.3 .2h-.3l-.2-.1M28.5 114.3l-.2 .8h.7M28.5 116.7l-.2 .8h.7M28.5 104.6l-.2 .9h.7M28.8 119.1l-.4 .1-.1 .3v.7l.5 .1 .2-.2v-.3l-.2-.2h-.4l-.1 .2M28.8 105.2v.7M28.8 114.7v.9M28.8 117.2v.7M28.9 111.9h-.6v.6l.4-.2 .3 .3v.3l-.2 .2-.5-.1M30.6 119.7h2.4M30.6 102.9h2.4"/>
<path d="M30.6 105.3h2.4M30.6 107.7h2.4M30.6 110.1h2.4M30.6 112.5h2.4M30.6 114.9h2.4M30.6 117.3h2.4M52.2 119.7h2.5M52.2 102.9h2.5M52.2 107.7h2.5M52.2 112.5h2.5M52.2 117.3h2.5M55.7 116.1h4.7v2.4h-4.7l-1-1.2z"/>
<path d="M55.7 118.5h5.7v2.4h-5.7l-1-1.2zM56.4 119.8l.6-.1v-.5l-.6-.1v1.2M56.6 119.8l.5 .5M57.1 116.8h-.5a.61 .61 0 0 0-.3 .7 .61 .61 0 0 0 .8 .4M58.2 116.8h-.6v.4l.6 .4-.2 .3h-.4M58.2 119.2l-.5-.1-.1 .2v.3l.6 .4-.1 .3h-.5M58.6 119.1h.7M58.7 116.8h.6v.3l-.7 .8h.7M58.9 119.1v1.2M59.6 119.5l.3-.4v1.2M82.3 101.9h2.4v4.8l-1.2 1-1.2-1zM83 104.1v.6h.5l.1-.5 .3-.1 .3 .3-.1 .4"/>
<path d="M83.1 105.2l-.1 .5a.67 .67 0 0 0 .6 .3 .67 .67 0 0 0 .6-.5l-.2-.3M83.5 113.7v1.2h3.6M83.5 107.7v1.2M84.2 103.3h-1.2l.3 .3M84.2 103v.6M90.7 117.9v4.2h1.2l-1.2 1.2-1.2-1.2h1.2M94.3 114.9h3.7M99 113.7h6.7v2.4h-6.7l-1-1.2zM100.3 114.5l-.2-.2a.65 .65 0 0 0-.5 .6 .65 .65 0 0 0 .5 .7l.2-.2M101.5 114.4l-.5-.1-.2 .2v.3l.7 .4-.2 .4-.5-.1M101.9 114.6l.4-.3v1.3M101.9 115.6h.7"/>
<path d="M102.9 115.7h.9M104 114.6h.1l.2-.3v1.3M104 115.6h.7M112.3 100.2h2.4v7.7l-1.2 1-1.2-1zM112.9 105.7h1.3M113 104.6l-.1 .5 .2 .1h.4l.4-.6 .3 .2-.1 .4M113 103.5l.8-.2 .3 .2 .1 .3-.2 .3h-.6l-.4-.1zM113.5 114.9v1.2h3.7M113.5 108.9v1.2M114.2 106.3h-1.3l1 .5-1 .4h1.3M114.2 101.6h-1.3l.4 .3M114.2 101.3v.6"/>
<path d="M114.3 102.2v.9M120.7 119.1v4.2h1.2l-1.2 1.2-1.2-1.2h1.2M124.4 116.1h3.5M129 114.9h5.6v2.4h-5.6l-1.1-1.2zM129.7 116.8v-1.2l.4 .8 .4-.8v1.2M131.1 115.6v1.2M132.2 115.6h-.5l-.1 .1 .1 .4 .5 .1v.4l-.1 .2-.5-.1M132.8 115.7l.1-.1h.4l.2 .1v.9l-.2 .2-.5-.2zM153.2 111.3v1.2h1.2l-1.2 1.2-1.2-1.2h1.2M156.5 112.5h7.7l1.1 1.2-1.1 1.2h-7.7zM157.6 114.3v-1.2l.5 .9 .4-.9v1.2M159 113.1v1.2"/>
<path d="M160.3 113.2l-.5-.1-.3 .3 .1 .2 .5 .2 .2 .3-.2 .2h-.6M160.9 113.1l.6 .2v.8l-.2 .2h-.4a.86 .86 0 0 1 0-1.2zM161.7 114.5h.9M162.9 113.5l.3-.4v1.2M162.9 114.3h.7M165.3 118.5h3.5M165.3 101.7h3.5M165.3 104.1h3.5M165.3 106.5h3.5M165.3 108.9h3.5M165.3 111.3h3.5M165.3 113.7h3.5"/>
<path d="M165.3 116.1h3.5M23.9 120.9h5.6l1.1 1.2-1.1 1.2h-5.6zM24 128.1h5.5l1.1 1.2-1.1 1.3h-5.5zM24 130.6h5.5l1.1 1.1-1.1 1.2h-5.5zM24.4 123.3h5.1l1.1 1.2-1.1 1.2h-5.1zM24.7 132.9h4.8l1.1 1.2-1.1 1.2h-4.8zM24.8 125.7h4.7l1.1 1.2-1.1 1.2h-4.7zM25.1 122.2l.6-.1v-.5h-.6v1.2M25.1 130v-1.2l.4 .8 .4-.8v1.2M25.1 132.3v-1.2l.4 .9 .4-.9v1.2M25.3 122.2l.4 .6M25.6 123.9v1.2"/>
<path d="M26.5 133.6h-.5l-.2 .2 .2 .3 .5 .2v.3l-.2 .2-.5-.1M26.5 131.1v1.2M26.6 128.8h.4a.74 .74 0 0 1 .2 1l-.5 .2a.86 .86 0 0 1-.1-1.2zM26.7 126.5l-.3-.2a.65 .65 0 0 0-.5 .7 .65 .65 0 0 0 .5 .6l.3-.2M26.8 121.6h-.5l-.1 .1 .1 .4 .5 .2v.3l-.1 .2-.5-.1M26.8 123.9v1.2l-.6-1.2v1.2M27.3 121.6h.6M27.3 123.9h.6M27.6 121.6v1.2M27.6 123.9v1.2M27.7 131.2h-.7v.5l.6 .1 .1 .2-.1 .3h-.6M27.8 133.7l-.5-.1-.3 .3 .1 .7 .3 .2 .4-.2"/>
<path d="M27.8 126.4l-.5-.1-.2 .3 .1 .2 .6 .3v.3l-.2 .2-.5-.1M28.2 131.3l.2-.2 .4 .1a.87 .87 0 0 1 0 1.1h-.5l-.2-.3zM28.3 126.7l.3-.4v1.3M28.3 133.6v1.2M28.3 127.6h.7M28.4 128.8h-.6a.47 .47 0 0 0 0 .5 .47 .47 0 0 0 .5 .2v.4h-.6M28.4 134.1l.6 .7M28.9 121.6h-.6v.5h.6l.1 .4-.3 .3-.4-.2M28.9 123.9h-.6v.6l.4-.1 .3 .2-.1 .4h-.6M28.9 128.8v1.2M29 133.6l-.7 .7M30.6 122.1h2.4"/>
<path d="M30.6 124.5h2.4M30.6 126.9h2.4M30.6 129.3h2.4M30.6 131.7h2.4M30.6 134.1h2.4M52.2 122.1h2.5M52.2 124.5h2.5M52.2 126.9h2.5M52.2 129.3h2.5M52.2 134.1h2.5M52.2 136.6h2.5M55.7 120.9h5.2v2.4h-5.2l-1-1.2z"/>
<path d="M55.7 123.3h4.7v2.4h-4.7l-1-1.2zM55.7 125.7h5.7v2.4h-5.7l-1-1.2zM55.7 128.1h5.2v2.5h-5.2l-1-1.3zM56.4 127l.6-.1v-.5l-.6-.1v1.3M56.4 121.6v1.2M56.4 128.8v1.2M56.6 127l.5 .6M57.1 124a.55 .55 0 0 0-.8 .5 .55 .55 0 0 0 .8 .5M57.7 121.6v1.2l-.7-1.2v1.2M57.7 128.8v1.2l-.7-1.2v1.2M58.1 121.6h.7M58.1 128.8h.7"/>
<path d="M58.2 124h-.6v.4l.6 .4-.2 .3-.4-.1M58.2 126.4l-.5-.1-.1 .2v.3l.5 .2 .1 .3-.2 .3-.4-.1M58.4 121.6v1.2M58.4 128.8v1.2M58.6 123.9h.7l-.4 .5 .4 .2v.4h-.7M58.6 126.3h.7M58.9 126.3v1.3M59.1 121.9l.3-.3v1.2M59.1 128.9l.6-.1 .1 .3-.8 .9h.8M59.1 122.8h.7M59.6 126.5l.4-.2 .3 .4-.8 .9h.8M59.6 120.3h.7"/>
<path d="M93.1 131.7v2.4h4.9M93.1 131.7l-.7 1.2M93.1 131.7l.7 1.2M112.3 134.1h4.9v1.2h1.2l-1.2 1.3-1.3-1.3h1.3M165.3 120.9h3.5M202.5 120.9h3.6M40.2 141.3v3.6h1.2l-1.2 1.2-1.2-1.2h1.2M42.7 141.3v2.5M45 141.3v2.5"/>
<circle cx="91.9" cy="98" r=".64"/>
<circle cx="120.7" cy="98" r=".64"/>
<circle cx="90.7" cy="117.3" r=".64"/>
<circle cx="120.7" cy="118.5" r=".64"/>
</g>
<g fill="none" stroke="#006665" stroke-width=".21">
<path d="M39.5 98.1l1.3 .4-1.3 .4M39.5 96.4h1.3l-1.3 .7h1.3M39.5 97.7h1.3M44.4 99.3v-.8l.5 .5 .1-.5h.4l.1 .2v.6M44.4 97.4l1.1 .5-1.1 .3M44.4 97.1v-.7l.5 .4 .1-.4h.5v.7M46.8 97.4v.6l.5 .1v-.7h.5l.2 .2v.4l-.2 .1M46.8 96.3l1.2 .4-1.2 .4M47.1 99.1h.9M47.5 98.6v1M169.6 98.6a.61 .61 0 0 1 .8 .6 .61 .61 0 0 1-.8 .6zM170.7 99.8l.3-1.2 .4 1.2"/>
<path d="M170.8 99.5h.6M171.7 98.6h.7M172 98.6v1.2M172.7 98.7l.4-.1 .3 .4-.8 .8h.8M33.8 102.2h.3l.4 .3v.6l-.4 .4h-.3zM33.8 104.6h.3l.4 .3v.7l-.4 .2h-.3zM33.8 107h.3l.4 .4v.5l-.2 .3h-.5zM33.8 109.5h.5l.2 .2v.6l-.4 .4h-.3zM33.8 111.8h.3l.4 .3v.7l-.2 .2h-.5zM33.8 114.2l.5 .1 .2 .3v.5l-.4 .4h-.3zM33.8 116.7h.5l.2 .2v.7l-.4 .3h-.3zM33.8 119h.3l.4 .4v.6l-.2 .2h-.5z"/>
<path d="M34.9 109.5h.7l-.4 .4 .4 .1v.6l-.6 .1-.1-.2M34.9 119h.8l-.5 1.2M35 105l.3-.4v1.2M35 107.2l.4-.2 .2 .4-.7 .8h.7M35 105.8h.6M35.2 102.2a.68 .68 0 0 1 .5 .6 .68 .68 0 0 1-.5 .7l-.2-.5v-.6zM35.2 111.8l-.2 .8h.7M35.6 114.2h-.6v.6l.6-.1v.7l-.5 .1-.1-.2M35.6 116.7l-.5 .1-.1 .8a.35 .35 0 0 0 .3 .3 .35 .35 0 0 0 .3-.3v-.3l-.2-.2-.4 .2M35.6 112.3v.7M37 102.2l-1 1.5M37 104.6l-1 1.5"/>
<path d="M37.3 104.6h.6M37.4 102.9l.6-.1v-.5l-.6-.1v1.3M37.6 104.6v1.2M37.7 102.9l.4 .6M38.2 104.6l.8 1.2M38.5 102.2l.8 1.3M39 104.6l-.8 1.2M39.3 102.2l-.8 1.3M46.4 101.9h5.2M46.6 102.9l.6-.1v-.4l-.1-.2h-.5v1.3M46.9 107v1.2M46.9 102.9l.3 .6"/>
<path d="M47.4 107.2l.3-.2 .5 .2v.8l-.2 .2h-.4l-.2-.2zM47.5 113l.4-1.2 .4 1.2M47.7 112.7h.5M47.8 102.8h.4M48.3 102.2h-.5v1.3h.5M48.7 107.7h.5l.2-.2v-.3l-.2-.2h-.5v1.2M48.7 112.4h.6l.1-.5-.7-.1v1.2M49 107.7l.4 .5M49 112.4l.4 .6M49.5 102.3l-.5-.1-.2 .2v.3l.7 .4-.2 .4-.5-.1M49.7 117.9l.4-1.2 .4 1.2M49.8 119.9h.6"/>
<path d="M49.8 117.5h.6M50 107.6h.3M50 112.4h.3M50 102.8h.5M50.5 107h-.5v1.2h.5M50.5 111.8h-.5v1.2h.5M50.6 102.2h-.6v1.3h.6M50.8 119.4h.2l.1-.4v1.2M51 116.7h.3l.2 .1v.8l-.4 .3a.84 .84 0 0 1-.1-1.2zM51 107.6h.4M51 102.2h.6M51 112.4h.4"/>
<path d="M51.3 102.2v1.3M51.6 107h-.6v1.2M51.6 111.8h-.6v1.2M169.4 105.8l.4 1.2 .5-1.2M169.4 110.7l.4 1.1 .5-1.1M169.6 117.9a.61 .61 0 0 1 .8 .5 .61 .61 0 0 1-.8 .6zM169.6 101a.66 .66 0 0 1 .7 .4 .66 .66 0 0 1-.2 .8h-.5zM169.6 113a.66 .66 0 0 1 .7 .4 .66 .66 0 0 1-.2 .8h-.5zM169.6 115.5h.5a.66 .66 0 0 1 .2 .8 .66 .66 0 0 1-.7 .4zM170.3 103.5h-.5l-.2 .2v.6l.2 .3h.3l.2-.1M170.3 108.4l-.4-.2-.3 .3v.6l.2 .3 .3 .1 .2-.2M170.7 102.2l.3-1.2 .4 1.2"/>
<path d="M170.7 105.8a.66 .66 0 0 1 .6 .5 .66 .66 0 0 1-.2 .7h-.4zM170.7 114.2l.3-1.2 .4 1.2M170.7 116.7l.3-1.2 .4 1.2M170.8 101.9h.6M170.8 113.9h.6M170.8 116.3h.6M170.9 104.6v-1.1l.3 .8 .4-.8v1.1M170.9 108.2v1.3h.5M170.9 118.4h.3M171.3 110.7h-.6a.47 .47 0 0 0 0 .5 .47 .47 0 0 0 .5 .1v.5h-.6M171.4 117.9h-.5v1.1h.5M171.7 117.9h.8"/>
<path d="M171.7 101h.7M171.7 113h.7M171.7 115.5h.7M171.8 108.2v1.3M171.9 105.8a.66 .66 0 0 1 .6 .5 .66 .66 0 0 1-.2 .7h-.4zM172 108.7l.5 .8M172 101v1.2M172 113v1.2M172 115.5v1.2M172 117.9v1.1M172.2 103.5h.4a.66 .66 0 0 1 .3 .7 .66 .66 0 0 1-.7 .4zM172.5 110.7h-.6l-.2 .2 .3 .3h.2l.3 .3-.1 .3h-.7"/>
<path d="M172.5 108.2l-.7 .8M172.5 119.2h1M172.6 101h.8l-.4 .5h.3v.7l-.7-.1M172.7 115.8l.4-.3v1.2M172.7 116.7h.7M173 113a.75 .75 0 0 1 .2 1.2h-.3l-.2-.4 .1-.6zM173.6 119l.4-1.1 .4 1.1M173.6 118.7h.6M174.7 101l-1 1.5M175.8 101.2l-.2-.2a.67 .67 0 0 0-.5 .5 .67 .67 0 0 0 .2 .7l.5-.1M176.4 101h.3l.3 .3v.6l-.1 .3h-.5zM33.8 121.5h.5l.2 .2v.6l-.4 .4h-.3z"/>
<path d="M33.8 123.9h.3l.4 .2v.7l-.4 .2h-.3zM33.8 126.2h.3l.4 .4v.6l-.4 .3h-.3zM33.8 128.7h.5l.2 .2v.7l-.4 .3h-.3zM33.8 131.1h.5l.2 .3v.6l-.2 .2h-.5zM33.8 133.5h.5l.2 .3v.6l-.4 .3h-.3zM35 126.6l.3-.4v1.3M35 129l.3-.3v1.2M35 131.4l.3-.3v1.1M35 133.9l.3-.4v1.2M35 127.5h.6M35 129.9h.6M35 132.2h.6"/>
<path d="M35 134.7h.6M35.2 122l-.2-.3v-.2h.6v.4l-.6 .1v.2v.2l.2 .3 .4-.3v-.4h-.2M35.6 124.4l-.4 .2-.2-.2v-.3a.35 .35 0 0 1 .3-.2 .35 .35 0 0 1 .3 .2l-.1 .9h-.5M36.1 129l.3-.3v1.2M36.1 131.1h.6v.5l-.6 .6h.6M36.1 133.5h.6l-.3 .4 .3 .1v.5l-.1 .2h-.4l-.1-.2M36.1 129.9h.6M36.2 126.3l.3-.1 .2 .3v.8l-.2 .2a.71 .71 0 0 1-.3-1.2zM39.5 138.7h1.3l-1.3 .7h1.3M39.6 140h-.1a.6 .6 0 0 0 .7 .6 .6 .6 0 0 0 .5-.6l-.4-.1v.2M39.7 137.5h.9l.2 .6h-1.3zM42 138.7h1.2l-1.2 .7h1.2"/>
<path d="M42.1 140a.54 .54 0 0 0 .5 .6 .54 .54 0 0 0 .5-.7h-.4v.2M42.2 137.5h.8l.2 .6h-1.2zM44.4 138.7h1.1l-1.1 .7h1.1M44.4 140a.66 .66 0 0 0 .4 .6 .66 .66 0 0 0 .7-.2v-.5h-.5v.2M44.5 137.5h.9l.1 .2v.4h-1.1zM45.9 126.3l-.5-.1-.3 .3 .1 .2 .7 .4-.3 .4-.5-.1M45.9 128.7h-.6l-.1 .2 .1 .3 .6 .3v.3h-.7M45.9 133.5h-.6l-.2 .2 .2 .3 .6 .4-.3 .3-.5-.1M45.9 136l-.4-.1-.3 .2 .1 .3 .6 .2v.4h-.7M46.4 126.2a.64 .64 0 0 1 .7 .7 .64 .64 0 0 1-.7 .6zM46.4 133.5h.4a.66 .66 0 0 1 .2 .8 .66 .66 0 0 1-.6 .4zM47.1 128.8l-.5-.1-.2 .2v.7a.45 .45 0 0 0 .7 .2"/>
<path d="M47.1 136a.45 .45 0 0 0-.7 .1v.7a.45 .45 0 0 0 .7 .2M47.4 127.5l.4-1.3 .4 1.3M47.4 134.7l.4-1.2 .4 1.2M47.5 127.1h.6M47.5 134.4h.6M47.7 128.7v1.2h.5M47.7 135.9v1.2h.5M49.4 126.2l-1 1.6M49.4 128.6l-1 1.5M49.4 133.4l-1 1.6M49.4 135.8l-1 1.5M49.7 120.2l.4-1.2 .4 1.2"/>
<path d="M49.7 122.7l.4-1.2 .4 1.2M49.7 125l.4-1.1 .4 1.1M49.7 127.5l.4-1.3 .4 1.3M49.7 129.9l.4-1.2 .4 1.2M49.7 134.7l.4-1.2 .4 1.2M49.7 137.1l.4-1.2 .4 1.2M49.8 122.3h.6M49.8 124.7h.6M49.8 127.1h.6M49.8 129.5h.6M49.8 134.4h.6M49.8 136.7h.6"/>
<path d="M50.8 121.6h.7v.4l-.7 .7h.7M50.8 123.9h.7l-.4 .4 .4 .2v.5h-.7M50.8 120.2h.7M51.1 126.2l-.3 .9h.8M51.1 133.4l-.3 .9h.8M51.4 126.7v.8M51.4 133.9v.8M51.5 128.7h-.6l-.1 .5h.7v.6h-.7M51.5 135.9h-.6l-.1 .6 .2-.2h.3l.2 .2v.5h-.7M99.1 133.5l.3 1.2 .4-1.2M100.9 133.6l-.5-.1a.67 .67 0 0 0-.2 .7 .67 .67 0 0 0 .5 .5l.2-.2M102.1 133.6l-.5-.1a.67 .67 0 0 0-.3 .7 .67 .67 0 0 0 .6 .5l.2-.2"/>
<path d="M108.6 133.5h-.5l-.2 .3v.6l.2 .2 .4 .1 .2-.2v-.3h-.2M109.9 133.5v1.2l-.7-1.2v1.2M110.4 133.5h.5a.66 .66 0 0 1 .2 .8 .66 .66 0 0 1-.7 .4zM169.6 120.2a.65 .65 0 0 1 .7 .7 .65 .65 0 0 1-.7 .6zM170.9 120.8h.3M171.4 120.2h-.5v1.3h.5M171.7 120.2h.8M172 120.2v1.3M172.5 121.6h1M173.7 120.8h.5l.2-.3-.2-.3h-.5v1.3h.5l.2-.2v-.4l-.2-.1M196.7 120.3l-.5-.1-.2 .2v.3l.5 .2 .2 .3-.3 .3-.4-.1M197.2 120.2v1.3"/>
<path d="M197.2 120.8h.7M197.9 120.2v1.3M198.5 120.2v1.3M199 120.8h.4M199.6 120.2h-.6v1.3h.6M200.1 120.2v1.3h.6M201.1 120.2a.64 .64 0 0 1 .7 .7 .64 .64 0 0 1-.7 .6z"/>
</g>
<g fill="none" stroke="#b90000" stroke-width=".21">
<path d="M65.7 41.6l.3-.4v1.2M65.7 43.7h.7v.4l-.7 .7h.7M65.7 46h.7l-.4 .5 .4 .1v.5h-.7M65.7 42.4h.7M66 48.3l-.3 .9h.8M66.3 48.8v.8M74.1 43.6h.7l-.5 1.2M74.3 41.7l-.1-.4 .5-.1 .1 .3-.2 .2-.4 .1v.4l.1 .2h.3l.2-.2v-.3l-.2-.2M74.7 46l-.4 .1-.1 .2v.8l.5 .1 .1-.2v-.4l-.1-.1h-.5v.1M74.8 48.4h-.6v.5l.4-.1 .2 .3v.4h-.6M104.1 46h.8l-.4 .5 .4 .1v.4l-.2 .2-.6-.1M104.2 41.6l.4-.4v1.2"/>
<path d="M104.2 43.7l.4-.1 .3 .3-.8 .9h.8M104.2 42.4h.7M104.5 48.3l-.3 .9h.7M104.7 48.8v.8M112.5 43.6h.9l-.5 1.2M112.9 41.7l-.3-.2 .1-.3h.5v.5h-.5l-.1 .2 .1 .4 .2 .1 .4-.2-.1-.5h-.2M113.2 48.4h-.5l-.1 .5h.6v.6h-.6M113.2 46h-.3a.93 .93 0 0 0-.2 1.2h.5l.1-.6-.1-.1h-.5l-.1 .1M179.8 46h.8l-.4 .5h.3l.1 .1-.1 .6-.7-.1M179.9 41.6l.4-.4v1.2M179.9 43.7l.4-.1 .3 .3-.8 .9h.8M179.9 42.4h.7"/>
<path d="M180.2 48.3l-.3 .9h.8M180.5 48.8v.8M188.3 43.6h.8l-.6 1.2M188.5 41.7l-.2-.3 .2-.2h.4l.1 .4-.7 .3v.3l.2 .2 .5-.2v-.4l-.2-.1M188.9 46l-.4 .1-.2 .9 .2 .2 .5-.1-.1-.6h-.4l-.2 .1M189 48.4h-.6l-.1 .5h.7v.6h-.7M218.3 46h.7l-.3 .5 .3 .1v.5h-.7M218.4 41.6l.3-.4v1.2M218.4 43.7h.6v.4l-.7 .7h.7M218.4 42.4h.6M218.7 48.3l-.3 .9h.7M218.9 48.8v.8"/>
<path d="M226.7 43.6h.8l-.5 1.2M227 41.7l-.2-.4 .5-.1 .2 .3-.3 .2-.4 .1v.4l.2 .2h.2l.3-.2v-.3l-.3-.2M227.3 46l-.3 .1-.2 .2v.8l.5 .1 .2-.2v-.4l-.2-.1h-.4l-.1 .1M227.4 48.4h-.6v.5l.4-.1 .3 .3-.1 .4h-.6M39.1 94.3l.2-.2h.4l.2 .2v.3l-.3 .2h-.2l-.3-.2-.1-.5-.4 .2v.3l.3 .2 .2-.2M43.9 94.2h.7M44.3 94.1v.7l-1-.3M45.8 94.1v.6l.6 .1v-.7h.5l.2 .2v.4l-.2 .1M86.2 94.1h.4l.3 .3-.8 .8h.8M91.5 99.6h-1.2l.4 .3M91.5 99.2v.7M96.9 94.1h.8l-.4 .5 .4 .1v.4l-.2 .1h-.6"/>
<path d="M115.7 94.1h-.6l-.1 .6 .6-.1 .1 .6h-.7M119.5 99.3h.9M120 99.1v.8l-.9-.3M126.4 94.1h-.4l-.2 1 .1 .1h.6l-.1-.6h-.5l-.1 .1M166.7 98l.3-.3v1.2M166.7 98.9h.7M30.9 101.6l.3-.3v1.1M30.9 104.1l.3-.4v1.2M30.9 106.4l.3-.3v1.2M30.9 108.9l.3-.4v1.2M30.9 111.2l.3-.3v1.2M30.9 113.5l.4-.2 .3 .3-.8 .9h.8"/>
<path d="M30.9 115.8l.6-.1 .1 .4-.8 .8h.8M30.9 118.2l.4-.1 .3 .3-.8 .9h.8M30.9 102.4h.7M30.9 104.9h.7M30.9 107.3h.7M30.9 109.7h.7M30.9 112.1h.7M32 106.1h.8l-.5 1.2M32.1 116.1l.3-.4v1.2M32.1 118.2l.4-.1 .3 .3-.8 .9h.8M32.1 116.9h.7M32.3 109l-.2-.4 .4-.1 .3 .3-.3 .2-.4 .1v.5l.2 .1h.2l.3-.2v-.3l-.3-.2"/>
<path d="M32.3 113.3a.71 .71 0 0 1 .3 1.2h-.3l-.2-.2v-.8zM32.6 103.7h-.3l-.2 .3v.8a.42 .42 0 0 0 .5 0 .42 .42 0 0 0 .1-.6l-.4-.1-.2 .3M32.7 101.3h-.6v.6l.5-.1 .2 .1v.4l-.2 .1h-.5M32.8 111.4l-.3 .3-.4-.2v-.5l.4-.1a.73 .73 0 0 1-.1 1.2h-.2M52.5 110.9h.8l-.5 .4 .5 .3-.1 .4h-.7M52.6 118.4l.3-.3v1.2M52.6 119.3h.7M53.1 106.2h.7v.4l-.7 .7h.7M53.1 101.3h.7l-.4 .5 .4 .1v.5h-.7M53.8 118.2l.3-.1a.86 .86 0 0 1 .1 1.2l-.4-.1zM53.8 111l.3-.1a.78 .78 0 0 1 0 1.2l-.3-.1zM53.8 116.2l-.1 .2h-.4l-.2-.2v-.3l.2-.2 .5 .1v.8l-.2 .2-.3 .1"/>
<path d="M85.7 113.8l-.3 .2h-.4l-.1-.5 .3-.2h.2a.81 .81 0 0 1 0 1.2h-.3M89.2 118a.61 .61 0 0 1 .7-.2 .61 .61 0 0 1 .4 .6 .7 .7 0 0 1-1.1-.1zM90.3 119.4h-1.1l.3 .3M90.3 119v.7M96 113.8l-.2-.3 .2-.2h.3l.1 .4-.4 .1-.2 .2 .1 .5 .5-.1v-.4l-.1-.2M114.5 114.8l.3-.3v1.2M114.5 115.7h.6M115.6 114.6l.1-.1h.4l.1 .1v.5l-.7 .6h.7M119.1 119.8v-.7l.5 .4 .1-.4h.5l.2 .2v.3l-.2 .2M125.2 114.8h.2l.2-.3v1.2M125.2 115.7h.7M126.4 114.8l.3-.3v1.2"/>
<path d="M126.4 115.7h.7M166.1 117.3l.4-.4v1.2M166.1 118.1h.7M166.6 102.4h.8l-.4 .6h.3v.6l-.5 .1-.2-.2M166.6 112.1h.9l-.6 1.2M166.7 100.2l.4-.1 .3 .3-.8 .9h.8M166.9 115.1l-.2-.5 .2-.1 .4 .1v.4l-.6 .1v.5l.2 .1h.2l.3-.2-.1-.4h-.2M167 104.8l-.3 .9h.8M167.3 107.3h-.6v.6l.6-.1v.7l-.6-.1M167.3 109.7h-.4l-.2 .3v.8h.6v-.6l-.4-.1-.2 .3M167.3 105.3v.8M167.4 117l.2-.1a.64 .64 0 0 1 .4 .6 .64 .64 0 0 1-.4 .6l-.3-.2z"/>
<path d="M167.4 119.8l-.3 .3-.4-.1v-.5l.4-.2 .3 .2-.2 .9-.4 .1M203.4 119.6l.3-.3v1.2M204.6 119.6l.3-.3v1.2M30.9 120.6l.4-.1 .3 .3-.8 .9h.8M30.9 123l.6-.1 .1 .4-.8 .8h.8M30.9 125.5l.4-.2 .3 .3-.8 .9h.8M30.9 127.8h.6l.1 .3-.8 .8h.8M30.9 130.2l.4-.1 .3 .4-.8 .8h.8M30.9 132.7l.4-.2 .3 .3-.8 1h.8M32 120.5h.8l-.5 .5 .4 .1 .1 .4-.3 .2h-.3l-.2-.1M32 130.1h.8l-.5 1.2M32.3 133l-.2-.1 .2-.4h.2l.3 .3-.2 .2h-.3l-.2 .2v.4l.2 .2h.2l.3-.3v-.2l-.3-.3"/>
<path d="M32.3 122.8l-.2 .9h.7M32.6 127.8h-.3l-.2 .2v.8l.4 .1 .3-.2v-.3l-.3-.2-.4 .1v.1M32.6 123.4v.7M32.7 125.3h-.6v.6l.5-.1 .2 .2v.3l-.2 .2-.5-.1M52.5 132.5h.8l-.5 .5 .5 .2v.3l-.3 .3h-.3l-.2-.2M52.5 135h.8l-.5 .4 .5 .2-.1 .5h-.7M52.6 120.8l.3-.3v1.2M52.6 123.3l.3-.4v1.2M52.6 125.6l.3-.3v1.2M52.6 128.1l.3-.3v1.1M52.6 121.7h.7M52.6 124.1h.7"/>
<path d="M52.6 126.5h.7M52.6 128.9h.7M53.6 125.3h.8l-.5 .5h.4l.1 .2-.1 .5-.7-.1M53.7 120.8l.3-.3v1.2M53.7 123l.6-.1 .1 .4-.8 .8h.8M53.7 132.8l.3-.3v1.3M53.7 135h.6l.1 .3-.8 .8h.8M53.7 121.7h.7M53.7 133.8h.7M53.9 127.7l-.2 .8h.7M54.3 128.1v.8M94.6 132.8h.1l.2-.3v1.3"/>
<path d="M94.6 133.8h.6M96 132.5l-.2 .8h.7M96.3 132.9v.9M114.4 132.5h.7l-.5 1.3M120.4 120.6h-1.3l.4 .3M120.4 120.2v.7M203.4 120.5h.6M204.6 120.5h.6M39.1 141.6l.3 .2-.1 .4h-.6l-.1-.4 .2-.2h.7l.3 .2 .1 .4M39.9 142.7v.8l-1-.8-.3 .3 .2 .4M41.1 142.3v.4l.9 .2 .2-.2v-.5h-.6l-.1 .5 .2 .2M44.6 142.7l-1.2-.5v.7"/>
</g>
<g fill="none" stroke="#090" stroke-width=".21">
<path d="M53.4 42.8v2.4h10.9M55.9 42.8h8.4M91.9 42.8v2.4h10.8M94.3 42.8h8.4M130.4 42.8v2.4h10.8M132.8 42.8h8.4M167.6 42.8v2.4h10.9M170 42.8h8.5M206.1 42.8v2.4h10.8M208.5 42.8h8.4M222.9 89.7v6M222.9 93.3h3.6v2.4"/>
<path d="M153.2 111.3h12.1M153.2 106.5h12.1M222.9 102.9v2.4h15.6M226.5 102.9h12M40.2 143.8h4.8"/>
</g>
<g fill="none" stroke="#0000ca" stroke-width=".21">
<path d="M41.4 32h206.8v44.5h-206.8zM131.4 25.7a.45 .45 0 0 0-.7 .1v.7l.2 .3 .5-.1M132 26l.5 .1-.1 .7h-.4zM133 26.1l.5-.1v.8M133 26v.8M134.1 26.1l.5-.1v.8M134.1 26v.8M135.1 26.3l.6-.1-.1-.2h-.4l-.1 .2 .1 .6h.4M136.7 26l-.5 .1v.6l.5 .1M137.1 26h.5M137.2 25.6v1l.1 .2h.3M137.9 26.3l.6-.1-.1-.2h-.4l-.1 .2 .1 .6h.4"/>
<path d="M139 26v.8l.5-.1M139.5 26v.8M140.1 26v.8M140.5 26h-.3l-.1 .2M141.2 26h-.4v.3h.3l.2 .2-.1 .3h-.4M143.3 26h-.6v.2v.6h.6M143.8 26h.4l.1 .2v.6h-.5v-.5l.5-.1M144.9 26v.8M145.2 26h-.3v.2M145.4 26h.5M145.5 25.6v1l.1 .2h.3M146.2 26.3l.6-.1-.1-.2h-.4l-.1 .2 .1 .6h.4"/>
<path d="M147.7 26h-.4l-.1 .2 .5 .3v.3h-.5M149 26h.4M149.4 25.6l-.2 .1v1.1M149.9 25.6v.1M149.9 26v.8M150.4 25.6v1l.2 .2M151 25.6v1l.2 .2M151.6 26.3l.6-.1-.1-.2h-.4l-.1 .2 .1 .6h.4M153.2 26h-.5v.2v.1l.5 .1v.4h-.5M18.6 81.3h49.3v72h-49.3zM72.6 81.3h67.4v62.5h-67.4zM144.8 81.3h66.1v55.3h-66.1z"/>
<path d="M215.7 81.3h52.9v44.4h-52.9zM171.9 139.3v1.2h.6M174.4 139.7l-.6 .1v.6h.6M174.7 139.7h.5M174.9 139.3v1.1l.3 .1M176.6 139.7v.6l.2 .2 .3-.1M177.1 139.7v.8M177.7 139.7v.8M178.1 139.7h-.3l-.1 .2M180 139.4h-.7v.3l.7 .4-.3 .4-.4-.1M180.5 139.3l.6 .1 .1 .4-.1 .5-.3 .2h-.3zM237.2 128.7v-1.2l.5 .9 .4-.9v1.2"/>
<path d="M238.6 128.3l.5-.1v-.3h-.5v.7h.5M239.6 128l.5-.1 .1 .8M239.6 127.9v.8M240.2 128.1v-.2h.4l.1 .8M241.2 128l.5-.1v.7h-.5zM242.3 127.5v.1M242.3 127.9v.8M242.9 127.9v.8M243.2 127.9h-.2l-.1 .2M243.6 128.3l.6-.1-.1-.3h-.4l-.1 .2v.4l.2 .2 .3-.1M33.2 155.7l.5-.1v-.4l-.5-.1v1.2h.5l.2-.3-.4-.3M34.4 155.6h.5l.1 .5-.2 .2h-.3l-.2-.2z"/>
<path d="M35.5 155.5v.8l.5-.1M36 155.5v.8M37.1 155.6a.36 .36 0 0 0-.6 .2l.1 .5h.5M37.6 155.1v1.2h.2M38.2 155.1v.2M38.2 155.5v.8M38.7 156l.6-.2-.2-.3-.4 .2v.4l.1 .2h.4M39.8 155.5v.8M40.1 155.5l-.3 .3M41.3 156.3l.4-1.2 .4 1.2M41.4 156h.6M42.5 155.5v.8"/>
<path d="M42.8 155.5l-.3 .3M43.8 155.1v1.2h-.5l-.1-.5a.36 .36 0 0 1 .6-.2M44.3 155.5l.1 .8 .5-.1M44.9 155.5v.8M45.4 155.1v.2M45.4 155.5v.8M46 155.6l.3-.1 .2 .2v.6M46 155.5v.8M47.1 155.6h.5l.1 .5-.2 .2h-.3l-.2-.2zM49.1 155.1l.1 1.2h.4l.2-.2v-1M50.3 155.6l.4-.1 .2 .2v.6M50.3 155.5v.8"/>
<path d="M51.4 155.6h.5v.7l-.5-.1zM91.8 145.6l-.5-.1a.61 .61 0 0 0-.3 .8 .61 .61 0 0 0 .8 .3M92.2 146.1l.4-.2 .3 .2-.1 .5h-.5zM93.4 146l.2-.1 .3 .1v.7M93.4 145.9v.8M94.3 145.9l.4 .8 .2-.8M95.3 146.3l.6-.1-.1-.3-.5 .1v.6l.2 .1 .3-.1M96.4 145.9v.8M96.8 145.9l-.4 .2M97.5 146l-.2-.1-.2 .2 .5 .5-.2 .1-.3-.1M98.1 145.5v.1M98.1 145.9v.8"/>
<path d="M98.7 146l.4-.1 .2 .2-.1 .5h-.5zM99.8 146l.2-.1 .3 .1v.7M99.8 145.9v.8M101.8 146l.1-.1 .4 .1v.7M101.8 145.9v.8M102.9 145.5v.1M102.9 145.9v.8M103.4 145.9l.2 .8 .3-.8M104.3 146.3l.6-.1-.2-.3-.4 .1v.6l.2 .1 .3-.1M105.4 146l.3-.1 .2 .1v.7M105.9 146.2l-.5 .1-.1 .2 .2 .2 .4-.1M106.5 145.9v.7h.5"/>
<path d="M107 145.9v.8M107.4 145.9l.7 .8M108.1 145.9l-.7 .8M109.5 145.5v1.1l.1 .1M110.1 146l.1-.1 .4 .1v.6h-.5zM111.7 145.9v1.1l-.2 .1h-.3M111.7 146l-.4-.1-.2 .2 .1 .5h.5M112.3 145.5v.1M112.3 145.9v.8M113.4 146h-.5l-.1 .5a.36 .36 0 0 0 .6 .1M113.4 145.9v1.2M114 145.9v.7h.5"/>
<path d="M114.5 145.9v.8M115 146.3l.6-.1-.1-.2h-.5v.6h.5M116.4 146l-.2-.1-.2 .2 .5 .5-.2 .1-.3-.1M172.8 140h.5v-.3h-.5v.7h.5M175.5 140h.6l-.1-.3h-.4l-.1 .2v.4l.2 .2 .3-.1"/>
</g>
<path d="M164.7 98.7l1.1 1.1M165.8 98.7l-1.1 1.1M164.7 115.5l1.1 1.2M164.7 117.9l1.1 1.2M165.8 115.5l-1.1 1.2M165.8 117.9l-1.1 1.2M164.7 120.3l1.1 1.2M165.8 120.3l-1.1 1.2" fill="none" stroke="#00008a" stroke-width=".21"/>
<g fill="#090">
<circle cx="223" cy="93.3" r=".47"/>
<circle cx="40.3" cy="143.8" r=".47"/>
<circle cx="42.7" cy="143.8" r=".47"/>
</g>
<g fill="none" stroke="#006665" stroke-width=".21">
<path d="M51.9 39.3h.9M52.3 38.8v.9M53.9 38.5h-.5l-.1 .6 .2-.2 .4 .1v.7l-.6-.1M54.4 38.5l.4 1.2 .4-1.2M69.8 39.7v1l-.4 .2M90.3 39.3h1M90.8 38.8v.9M92.5 38.5h-.6l-.1 .6 .1-.2h.4l.2 .2v.5h-.7M92.8 38.5l.4 1.2 .4-1.2M108.4 39.7v.9l-.2 .3h-.3M108.9 39.9l.4-.2 .3 .3-.8 .9h.8M128.9 39.3h.8"/>
<path d="M129.3 38.8v.9M130.9 38.5h-.6l-.1 .6 .5-.2 .3 .3v.3l-.2 .2-.6-.1M131.3 38.5l.4 1.2 .4-1.2M146.8 39.7v.9l-.2 .3h-.3M147.6 39.7l-.3 .9h.8M166.1 39.3h.9M166.5 38.8v.9M168.1 38.5h-.5v.6l.4-.2 .2 .3v.3l-.1 .2-.5-.1M168.6 38.5l.3 1.2 .4-1.2M184.1 39.7v.9l-.2 .3h-.3M185.2 39.7h-.5l-.1 .6 .6-.1v.7l-.6-.1M204.6 39.3h.9"/>
<path d="M205 38.8v.9M206.6 38.5h-.6v.6l.4-.2 .3 .3-.1 .5-.6-.1M207 38.5l.4 1.2 .4-1.2M222.5 39.7v1l-.4 .2M223.6 39.7l-.4 .2-.2 .8 .2 .2 .5-.1-.1-.6h-.4l-.2 .2M54.9 47h-.5l-.1 .2v.6l.1 .3 .4 .1 .2-.2v-.3h-.2M56.2 46.9v1.3l-.7-1.3v1.3M56.8 46.9a.64 .64 0 0 1 .7 .6 .64 .64 0 0 1-.7 .7zM67 58.4h.5l.1-.2v-.3l-.1-.2h-.5v1.2M67.3 58.4l.3 .5M68.2 57.9l.4-.2 .2 .4-.7 .8h.7M70.4 40h.1l.2-.3v1.2"/>
<path d="M70.4 40.9h.7M75.3 58.9v1.3h.5M75.7 56.6l.7 .2v.7l-.2 .2h-.5zM76.2 59.5h.4M76.8 58.9h-.6v1.3h.6M76.9 56.9l.3-.3v1.1M76.9 57.7h.7M77.3 58.9a.64 .64 0 0 1 .7 .7 .64 .64 0 0 1-.7 .6zM93.4 47l-.1-.1a.64 .64 0 0 0-.6 .6 .64 .64 0 0 0 .5 .7l.3-.2v-.3h-.3M94.7 46.9v1.3l-.7-1.3v1.3M95.2 46.9a.64 .64 0 0 1 .7 .6 .64 .64 0 0 1-.7 .7zM105.4 58.4h.5l.3-.4-.3-.3h-.5v1.2"/>
<path d="M105.7 58.4l.5 .5M107.2 57.7h-.3a.93 .93 0 0 0-.2 1.2h.5l.1-.5-.1-.2h-.5l-.1 .2M113.7 58.9v1.3h.6M114.1 56.6h.4l.3 .2v.7l-.2 .2h-.5zM114.6 59.5h.5M115.2 58.9h-.6v1.3h.6M115.3 56.6h.4l.3 .3-.8 .8h.8M115.7 58.9h.4l.3 .4v.6l-.3 .3h-.4zM131.8 47l-.1-.1a.6 .6 0 0 0-.6 .6 .6 .6 0 0 0 .7 .6l.1-.4h-.2M133.1 46.9v1.3l-.7-1.3v1.3M133.7 46.9a.64 .64 0 0 1 .7 .6 .64 .64 0 0 1-.7 .7zM143.9 58.4h.5l.2-.4-.2-.3h-.5v1.2"/>
<path d="M144.2 58.4l.4 .5M145 57.7h.8l-.5 1.2M147.9 40.1v.8M152.1 58.9v1.3h.6M152.7 56.6a.66 .66 0 0 1 .6 .4 .66 .66 0 0 1-.2 .7h-.4zM153.2 59.5h.3M153.7 58.9h-.5v1.3h.5M153.7 56.6h.7l-.3 .4 .3 .1v.6h-.7M154.3 58.9a.64 .64 0 0 1 .6 .7 .64 .64 0 0 1-.6 .6zM169.1 47l-.1-.1a.6 .6 0 0 0-.6 .6 .6 .6 0 0 0 .7 .6l.1-.4h-.3M170.3 46.9v1.3l-.6-1.3v1.3M170.9 46.9a.52 .52 0 0 1 .7 .3v.6a.52 .52 0 0 1-.7 .4z"/>
<path d="M181.2 58.4l.6-.1v-.5l-.6-.1v1.2M181.4 58.4l.5 .5M182.5 58.2l-.2-.2 .2-.3h.3l.2 .5h-.5l-.2 .3 .2 .4 .5-.1v-.4l-.2-.2M189.4 58.9v1.3h.6M189.9 56.6a.66 .66 0 0 1 .7 .4 .66 .66 0 0 1-.3 .7h-.4zM190.4 59.5h.4M191 58.9h-.6v1.3h.6M191.3 56.5l-.3 .8h.8M191.5 58.9a.64 .64 0 0 1 .7 .7 .64 .64 0 0 1-.7 .6zM191.6 57v.7M207.6 47l-.3-.1-.4 .3v.6l.2 .3h.5v-.4h-.2M208.9 46.9v1.3l-.7-1.3v1.3"/>
<path d="M209.4 46.9h.3l.4 .3v.6l-.4 .4h-.3zM219.6 58.4l.6-.1v-.5l-.6-.1v1.2M219.9 58.4l.4 .5M221.5 58.2l-.3 .3-.4-.1v-.5l.4-.2a.81 .81 0 0 1 0 1.2h-.3M227.9 58.9v1.3h.5M228.3 56.6a.66 .66 0 0 1 .7 .4 .66 .66 0 0 1-.2 .7h-.5zM228.9 59.5h.4M229.4 58.9h-.5v1.3h.5M230 58.9a.64 .64 0 0 1 .6 .7 .64 .64 0 0 1-.6 .6zM230.1 56.6h-.6l-.1 .5 .6-.1 .2 .2-.1 .5h-.7M67.1 60.5l.3-.3v1.2M67.1 61.4h.6"/>
<path d="M68.2 60.2v1.2M68.3 60.9l.4 .5M68.7 60.5l-.5 .5M77.8 67.4h-.5l-.2 .2v.7a.45 .45 0 0 0 .7 .2v-.4h-.2M79 67.4v1.2l-.7-1.2v1.2M79.6 67.4h.5l.2 .2v.7l-.4 .3h-.3zM105.5 60.5l.3-.3v1.2M105.5 61.4h.7M106.7 60.2v1.2M106.8 60.9l.4 .5M107.2 60.5l-.5 .5M116.2 67.4h-.5l-.1 .2v.7a.52 .52 0 0 0 .7 .2v-.4h-.2"/>
<path d="M117.5 67.4v1.2l-.7-1.2v1.2M118.1 67.4h.4a.66 .66 0 0 1 .3 .7 .66 .66 0 0 1-.7 .5zM143.9 60.5l.4-.3v1.2M143.9 61.4h.7M145.2 60.2v1.2M145.3 60.9l.3 .5M145.6 60.5l-.4 .5M154.7 67.4h-.4a.61 .61 0 0 0-.3 .8 .61 .61 0 0 0 .8 .3v-.4h-.3M156 67.4v1.2l-.7-1.2v1.2M156.5 67.4h.5a.66 .66 0 0 1 .2 .7 .66 .66 0 0 1-.7 .5zM181.2 60.5l.4-.3v1.2M181.2 61.4h.7"/>
<path d="M182.5 60.2v1.2M182.5 60.9l.4 .5M182.9 60.5l-.4 .5M191.9 67.4h-.4a.61 .61 0 0 0-.2 .8 .61 .61 0 0 0 .7 .3v-.4h-.2M193.2 67.4v1.2l-.7-1.2v1.2M193.8 67.4h.4a.66 .66 0 0 1 .3 .7 .66 .66 0 0 1-.7 .5zM219.7 60.5l.3-.3v1.2M219.7 61.4h.7M220.9 60.2v1.2M221 60.9l.3 .5M221.3 60.5l-.4 .5M230.4 67.4h-.4a.61 .61 0 0 0-.3 .8 .61 .61 0 0 0 .8 .3v-.4h-.3"/>
<path d="M231.6 67.4v1.2l-.6-1.2v1.2M232.2 67.4h.5l.2 .2v.7l-.4 .3h-.3zM42.9 87.4h1M43.3 86.9v.9M44.3 86.6h.7l-.4 .4 .4 .1v.6h-.7M45.4 86.6l.4 1.2 .3-1.2M45.9 89.7h.9M46.3 89.3v.9M46.5 86.6h.7l-.4 .4 .4 .3v.4h-.7M47.9 89h-.5l-.1 .6 .6-.1v.7l-.6-.1M48.3 89l.5 1.2 .4-1.2M81.6 94.2v-.7l.5 .3 .1-.3h.5v.7"/>
<path d="M81.6 92.5v-.8l.5 .4 .2-.4h.3l.2 .2-.1 .6M81.6 91.2h1.2M82 90.8l.5 .4M82.7 93h.1M82.8 90.8l-.4 .3M86.3 92l.6-.1v-.4l-.6-.1v1.2M86.6 92l.3 .6M87.5 91.8l.3-.4v1.2M87.5 92.6h.6M89.2 95v1l.2 .2h.4l.2-.2v-1M90.5 95.3l.3-.3v1.2M90.5 96.2h.7"/>
<path d="M91.5 96.2l.4-1.2 .4 1.2M91.6 95.8h.6M110.5 94.2v-.7l.4 .3 .2-.3h.5v.7M110.5 92.5v-.8l.4 .4 .3-.4 .4 .1v.7M110.5 91.2h1.2M110.9 90.8l.4 .4M111.6 93h.1M111.7 90.8l-.5 .3M115.1 92l.6-.1v-.5h-.6v1.2M115.4 92l.4 .6M116.2 91.4h.8l-.4 .5h.3v.6h-.7M118 95v1l.2 .2 .5-.1v-1.1"/>
<path d="M119.2 95.3h.2l.1-.3v1.2M119.2 96.2h.7M120.5 95.6l.5-.1v-.4l-.5-.1v1.2h.5l.2-.4-.4-.2M178.7 92.6v-1.2l.4 .9 .4-.9v1.2M180.1 91.4v.1M180.1 91.8v.8M181.2 91.9h-.5l-.1 .5a.36 .36 0 0 0 .6 .1M181.7 91.8v.8M182 91.8l-.3 .2M182.5 91.9l.3-.1 .2 .1v.6h-.5zM183.2 92.7h.9M185.1 91.4h-.6l-.1 .5a.57 .57 0 0 1 .6 .6h-.6"/>
<path d="M185.6 91.4h.4a.66 .66 0 0 1 .2 .8 .66 .66 0 0 1-.6 .4zM186.5 92.7h.9M187 89v1l-.4 .2M187.8 89.5l-.3-.3 .3-.2h.2l.3 .3-.8 .4 .2 .5h.4l.2-.2v-.3l-.3-.2M188.4 91.5l-.5-.1a.67 .67 0 0 0-.3 .7 .67 .67 0 0 0 .5 .5l.3-.1M188.9 91.9l.3-.1 .2 .1v.7M189.4 92.1h-.4l-.2 .2 .2 .3 .4-.1M190 91.8v.8M190.3 91.8l-.3 .2M191.3 91.9h-.5l-.1 .5a.36 .36 0 0 0 .6 .1M191.3 91.4v1.2M191.5 92.7h.9"/>
<path d="M192.7 91.4h.5l.2 .3v.6l-.4 .3h-.3zM193.9 92.2l.6-.1-.2-.3-.4 .1v.6l.2 .1 .3-.1M194.8 91.8h.4M195 91.4v1.1l.2 .1M195.6 91.5l.6-.1 .1 .5-.8 .7h.8M217.2 89.7h.9M217.7 89.3v.9M218.4 99l.4-.4v1.2M218.4 99.8h.7M218.6 89h.7l-.4 .5 .4 .1v.5h-.7M219.6 89l.4 1.2 .5-1.2M219.7 98.7l.3-.1a.64 .64 0 0 1 .3 .7 .64 .64 0 0 1-.4 .5l-.3-.2z"/>
<path d="M220.7 89h.8l-.4 .5h.3v.7l-.7-.1M220.8 98.6v1.2M220.9 99.4l.3 .4M221.2 99.1l-.4 .4M223.4 99.3h-1.2l.4 .3M223.4 98.2h-1.2l.4 .2v.1M223.4 97.9v.6M223.4 99v.6M225.9 98l.2-.1h.7l.3 .2a.64 .64 0 0 1-.6 .5 .64 .64 0 0 1-.6-.4zM227.1 99.3h-1.2l.3 .3M227.1 99v.6M228.3 97.3l.4-.4v1.2"/>
<path d="M228.3 98.1h.7M229.5 97l.4-.1a.78 .78 0 0 1 0 1.2l-.4-.1zM230.6 96.9v1.2M230.8 97.7l.3 .4M231.1 97.4l-.5 .4M242.4 95.8h.9M242.9 95.3v.9M243.8 95h.7l-.3 .5 .3 .1v.5h-.7M244.9 95l.4 1.2 .4-1.2M246 95h.7l-.4 .5h.3v.7l-.6-.1M257.1 97.4l.5-1.1 .3 1.1M257.2 97.1h.6"/>
<path d="M258.1 96.3h.7M258.5 96.3v1.1M259.5 96.2l-.3 .8h.7M259.8 96.7v.7M260.9 96.3h-.6v.6l.5-.2 .2 .2-.1 .5h-.6M261.5 96.3h.5a.66 .66 0 0 1 .2 .7 .66 .66 0 0 1-.7 .4zM261.7 93.8v1.1l.2 .2h.2l.3-.3v-1M262.7 96.9h.4l.2-.2-.1-.4h-.5v1.1h.6l.1-.4-.3-.1M262.9 94l.4-.2 .3 .3-.8 1h.8M264.4 96.3h-.3l-.2 .2v.9h.6l.1-.5-.3-.2h-.2l-.2 .2M265.3 96.2l-.3 .8h.8M265.6 96.7v.7"/>
<path d="M266.2 96.6l.3-.3v1.1M266.2 97.4h.7M267.4 96.9h.4M268 96.3h-.6v1.1h.6M39.5 119h.2M39.5 114.6h1.1l.2 .3-.2 .4h-1.1M39.5 113.4h1.3l-1.3 .6h1.3M39.5 109.6v-.8l.5 .4 .1-.3h.6l.1 .5-.2 .2M39.6 112.2l.8-.2a.46 .46 0 0 1 .4 .6 .86 .86 0 0 1-1.3 0zM40 119.5h.8M40 119h.8M40 118.4h.8"/>
<path d="M40 116.8h.6l.2 .4-.2 .1h-.5l-.1-.1zM40.2 110.7l-.1-.7-.3-.1-.3 .2v.6h1.3M40.6 119.5l.2 .2-.2 .4h-.6M40.8 117.9h-.7l-.1 .1 .1 .4M40.8 109.9l-.6 .4M40.9 110.9v.9M40.9 115.6v.9M41.7 117.9l.4-1.2 .3 1.2M41.7 117.5h.6M42.8 117l.4-.3v1.2M42.8 117.9h.7M80.4 113.5v-.8l.5 .4v-.3l.2-.1 .5 .1-.1 .7"/>
<path d="M80.4 111.7v-.7l.5 .3 .1-.3h.5v.7M80.4 110.4h1.2M80.9 110l.4 .4M81.5 112.2h.1M81.6 110l-.4 .3M85.1 111.2h.6v-.5h-.6v1.1M85.3 111.2l.5 .6M86.5 110.6l-.2 .8h.6M86.8 111.1v.7M88 114.2v1l.2 .3 .4-.2v-1.1M89.2 114.6l.4-.4v1.3M89.2 115.5h.7"/>
<path d="M91 105.9a.45 .45 0 0 0-.7 .2v.7l.2 .2h.5v-.5h-.2M91.1 114.4l-.3-.2a.65 .65 0 0 0-.5 .6 .65 .65 0 0 0 .5 .7l.3-.2M92.3 105.8v1.2l-.7-1.2v1.2M92.8 105.8a.66 .66 0 0 1 .7 .4 .66 .66 0 0 1-.2 .8h-.5zM110.5 114.6v-.7l.4 .4 .3-.4 .5 .1-.1 .6M110.5 112.9v-.7l.4 .4 .2-.4h.5v.7M110.5 111.7h1.2M110.9 111.2l.4 .5M111.6 113.4h.1M111.7 111.2l-.5 .3M115.1 112.4h.6v-.5l-.6-.1v1.2M115.4 112.4l.4 .6"/>
<path d="M116.9 111.8h-.6l-.1 .6 .2-.1h.4l.2 .2-.1 .4h-.7M118 115.5v.9l.3 .3 .4-.2v-1M119.2 115.8l.3-.3v1.2M119.2 116.7h.7M119.8 105.9a.59 .59 0 0 0-.7 .4 .59 .59 0 0 0 .3 .7l.5-.1v-.4h-.3M120.5 115.5h.4a.66 .66 0 0 1 .2 .7 .66 .66 0 0 1-.6 .5zM121.1 105.8v1.2l-.7-1.2v1.2M121.7 105.8l.6 .3v.7l-.1 .2h-.5zM147.5 106.6h.9M147.9 106.1v.9M148.8 105.8h.8l-.4 .5 .4 .2-.1 .5-.7-.1M149.9 105.8l.5 1.2 .3-1.2"/>
<path d="M151 105.8h.8l-.4 .5 .4 .2v.3l-.2 .2-.6-.1M152.3 115.5h-.5l-.2 .2v.6l.2 .3h.5v-.4h-.2M153.6 115.5v1.2l-.7-1.2v1.2M154.1 115.5h.5l.2 .2v.6l-.4 .4h-.3zM222.9 100.8v-.5l-.1-.1h-.4l-.2 .1v.5h1.2M223.4 100.2l-.5 .3M226.5 100.8v-.6h-.5l-.1 .6h1.2M227.1 100.2l-.6 .3M247.2 119.1l-.1-.1a.66 .66 0 0 0-.5 .5 .66 .66 0 0 0 .2 .7l.5-.1v-.4h-.2M248.5 119v1.2l-.7-1.2v1.2M249.1 119a.66 .66 0 0 1 .6 .5 .66 .66 0 0 1-.2 .7h-.4zM39.5 120.6h1.3"/>
<path d="M40 121.6l.2 .3M40 121.9h.8M40 120.6v.4l.2 .2h.4l.2-.2-.1-.4M40.5 122.4v.6M40.8 122.3l-1.3 .4 1.3 .4M89.8 125.1l-.1-.1a.66 .66 0 0 0-.6 .5 .66 .66 0 0 0 .2 .7h.5v-.5h-.1M91 125v1.2l-.7-1.2v1.2M91 130.6h.9M91.4 130.1v1M91.6 125h.3l.4 .4v.6l-.2 .2h-.5zM92.4 129.9h.7l-.4 .4 .4 .3-.1 .4h-.6M93.5 129.9l.4 1.2 .3-1.2"/>
<path d="M94.6 129.9h.6l-.3 .4 .3 .2v.5h-.6M100.8 127.5h.8l-.5 1.2M102.4 127.4l-.4 .9h.8M102.6 127.8v.9M103.2 127.5v1.2h.6M103.6 125v1.1l.2 .1h.4l.2-.1v-1.1M104.1 127.5l.4 1.2 .3-1.2M104.9 125.4l.3-.4v1.2M104.9 126.2h.7M105.9 127.6l-.5-.1a.67 .67 0 0 0-.2 .7 .67 .67 0 0 0 .5 .5l.2-.2M106.1 125.6h.4M106.4 127.8l.4-.3v1.2"/>
<path d="M106.4 128.7h.7M106.7 125h-.6v1.2h.6M107.5 127.6l.6-.1 .1 .5-.8 .7h.8M109.3 127.5h-.6v.5h.6l.1 .4-.3 .3-.4-.2M116.2 138.3h-.3l-.3 .3v.6l.1 .2h.6v-.5h-.2M117.5 138.3v1.1l-.7-1.1v1.1M118.1 138.3a.66 .66 0 0 1 .7 .4 .66 .66 0 0 1-.3 .7h-.4zM119.8 126.3l-.1-.1a.64 .64 0 0 0-.6 .6 .64 .64 0 0 0 .5 .7l.3-.2v-.4h-.3M121.1 126.2v1.3l-.7-1.3v1.3M121.7 126.2a.52 .52 0 0 1 .6 .4v.6a.52 .52 0 0 1-.6 .3zM205.1 125.1v-.1a.66 .66 0 0 0-.6 .5 .66 .66 0 0 0 .2 .7h.5v-.5h-.2M206.4 125v1.2l-.7-1.2v1.2"/>
<path d="M207 125a.66 .66 0 0 1 .7 .5 .66 .66 0 0 1-.3 .7h-.4zM39.3 148a.54 .54 0 0 0-.7 .6 .54 .54 0 0 0 .8 .4v-.4h-.3M40.6 147.9v1.2l-.7-1.2v1.2M41.1 147.9l.6 .2 .1 .3-.1 .5-.3 .2h-.3z"/>
</g>
<g fill="none" stroke="#b54549" stroke-width=".21">
<circle cx="40.3" cy="93.3" r=".38"/>
<circle cx="30.7" cy="102.9" r=".38"/>
<circle cx="54.7" cy="102.9" r=".38"/>
<circle cx="54.7" cy="107.7" r=".38"/>
<circle cx="54.7" cy="112.6" r=".38"/>
<circle cx="54.7" cy="134.1" r=".38"/>
<circle cx="54.7" cy="136.6" r=".38"/>
</g>
</svg>
